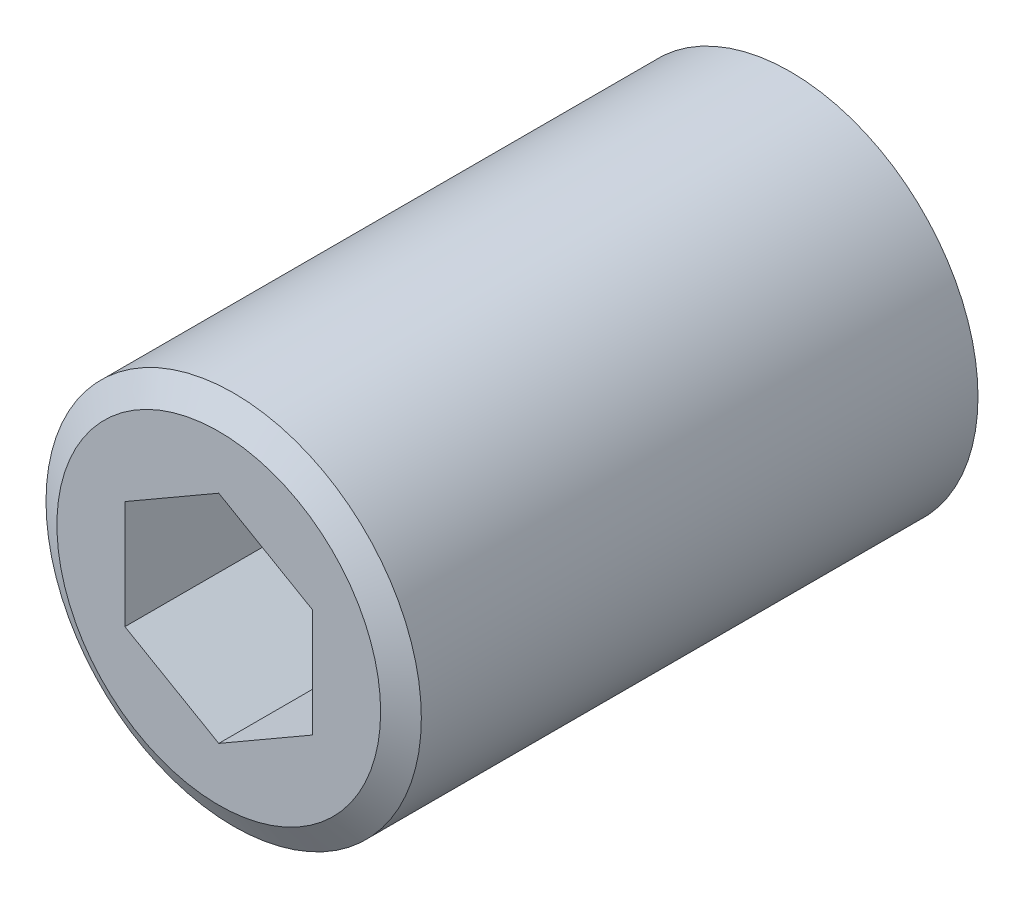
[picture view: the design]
ISO-10303-21;
HEADER;
FILE_DESCRIPTION(('STEP AP214'),'2;1');
FILE_NAME('part.step','',(''),(''),'','','');
FILE_SCHEMA(('AUTOMOTIVE_DESIGN { 1 0 10303 214 1 1 1 1 }'));
ENDSEC;
DATA;
#1=APPLICATION_CONTEXT('core data for automotive mechanical design processes');
#2=APPLICATION_PROTOCOL_DEFINITION('international standard','automotive_design',2000,#1);
#3=PRODUCT_CONTEXT('',#1,'mechanical');
#4=PRODUCT('Part','Part','',(#3));
#5=PRODUCT_RELATED_PRODUCT_CATEGORY('part','',(#4));
#6=PRODUCT_DEFINITION_FORMATION('','',#4);
#7=PRODUCT_DEFINITION_CONTEXT('part definition',#1,'design');
#8=PRODUCT_DEFINITION('design','',#6,#7);
#9=PRODUCT_DEFINITION_SHAPE('','',#8);
#10=(LENGTH_UNIT() NAMED_UNIT(*) SI_UNIT(.MILLI.,.METRE.));
#11=(NAMED_UNIT(*) PLANE_ANGLE_UNIT() SI_UNIT($,.RADIAN.));
#12=(NAMED_UNIT(*) SI_UNIT($,.STERADIAN.) SOLID_ANGLE_UNIT());
#13=UNCERTAINTY_MEASURE_WITH_UNIT(LENGTH_MEASURE(1.E-05),#10,'distance_accuracy_value','');
#14=(GEOMETRIC_REPRESENTATION_CONTEXT(3) GLOBAL_UNCERTAINTY_ASSIGNED_CONTEXT((#13)) GLOBAL_UNIT_ASSIGNED_CONTEXT((#10,
#11,#12)) REPRESENTATION_CONTEXT('',''));
#15=CARTESIAN_POINT('',(0.,0.,0.));
#16=DIRECTION('',(0.,0.,1.));
#17=DIRECTION('',(1.,0.,0.));
#18=AXIS2_PLACEMENT_3D('',#15,#16,#17);
#19=CARTESIAN_POINT('',(1.5,-5.55,0.));
#20=DIRECTION('',(-0.707106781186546,0.,0.707106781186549));
#21=DIRECTION('',(0.707106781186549,0.,0.707106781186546));
#22=AXIS2_PLACEMENT_3D('',#19,#20,#21);
#23=PLANE('',#22);
#24=CARTESIAN_POINT('',(0.,0.,-1.5));
#25=DIRECTION('',(-0.707106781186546,0.,0.707106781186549));
#26=DIRECTION('',(-0.707106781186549,0.,-0.707106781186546));
#27=AXIS2_PLACEMENT_3D('',#24,#25,#26);
#28=ELLIPSE('',#27,7.84888527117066,5.55);
#29=CARTESIAN_POINT('',(3.,4.66931472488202,1.5));
#30=VERTEX_POINT('',#29);
#31=CARTESIAN_POINT('',(2.77,4.80932427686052,1.27));
#32=VERTEX_POINT('',#31);
#33=EDGE_CURVE('E39',#30,#32,#28,.T.);
#34=ORIENTED_EDGE('',*,*,#33,.F.);
#35=DIRECTION('',(0.,1.,0.));
#36=VECTOR('',#35,1.);
#37=CARTESIAN_POINT('',(3.,-5.55,1.5));
#38=LINE('',#37,#36);
#39=CARTESIAN_POINT('',(3.,3.01132144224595,1.5));
#40=VERTEX_POINT('',#39);
#41=EDGE_CURVE('E747',#40,#30,#38,.T.);
#42=ORIENTED_EDGE('',*,*,#41,.F.);
#43=DIRECTION('',(-0.577350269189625,0.577350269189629,-0.577350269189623));
#44=VECTOR('',#43,1.);
#45=CARTESIAN_POINT('',(4.853773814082,1.15754762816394,3.353773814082));
#46=LINE('',#45,#44);
#47=CARTESIAN_POINT('',(1.51132144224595,4.5,0.0113214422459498));
#48=VERTEX_POINT('',#47);
#49=EDGE_CURVE('E390',#40,#48,#46,.T.);
#50=ORIENTED_EDGE('',*,*,#49,.T.);
#51=DIRECTION('',(0.57735026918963,0.57735026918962,0.577350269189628));
#52=VECTOR('',#51,1.);
#53=CARTESIAN_POINT('',(-1.846226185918,1.1424523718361,-3.34622618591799));
#54=LINE('',#53,#52);
#55=CARTESIAN_POINT('',(2.13446219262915,5.12314075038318,0.634462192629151));
#56=VERTEX_POINT('',#55);
#57=EDGE_CURVE('E743',#48,#56,#54,.T.);
#58=ORIENTED_EDGE('',*,*,#57,.T.);
#59=CARTESIAN_POINT('',(0.,0.,-1.5));
#60=DIRECTION('',(-0.707106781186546,0.,0.707106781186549));
#61=DIRECTION('',(0.707106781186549,0.,0.707106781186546));
#62=AXIS2_PLACEMENT_3D('',#59,#60,#61);
#63=ELLIPSE('',#62,7.84888527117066,5.55);
#64=EDGE_CURVE('E800',#32,#56,#63,.T.);
#65=ORIENTED_EDGE('',*,*,#64,.F.);
#66=EDGE_LOOP('',(#34,#42,#50,#58,#65));
#67=FACE_BOUND('',#66,.T.);
#68=ADVANCED_FACE('F15',(#67),#23,.F.);
#69=CARTESIAN_POINT('',(1.5,-5.55,0.));
#70=DIRECTION('',(0.707106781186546,0.,0.707106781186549));
#71=DIRECTION('',(0.707106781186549,0.,-0.707106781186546));
#72=AXIS2_PLACEMENT_3D('',#69,#70,#71);
#73=PLANE('',#72);
#74=CARTESIAN_POINT('',(0.,0.,1.5));
#75=DIRECTION('',(0.707106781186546,0.,0.707106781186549));
#76=DIRECTION('',(0.707106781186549,0.,-0.707106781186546));
#77=AXIS2_PLACEMENT_3D('',#74,#75,#76);
#78=ELLIPSE('',#77,7.84888527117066,5.55);
#79=CARTESIAN_POINT('',(0.22999999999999,5.54523218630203,1.27));
#80=VERTEX_POINT('',#79);
#81=CARTESIAN_POINT('',(0.,5.55,1.5));
#82=VERTEX_POINT('',#81);
#83=EDGE_CURVE('E476',#80,#82,#78,.T.);
#84=ORIENTED_EDGE('',*,*,#83,.F.);
#85=CARTESIAN_POINT('',(0.,0.,1.5));
#86=DIRECTION('',(0.707106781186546,0.,0.707106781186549));
#87=DIRECTION('',(-0.707106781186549,0.,0.707106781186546));
#88=AXIS2_PLACEMENT_3D('',#85,#86,#87);
#89=ELLIPSE('',#88,7.84888527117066,5.55);
#90=CARTESIAN_POINT('',(0.457573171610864,5.53110538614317,1.04242682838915));
#91=VERTEX_POINT('',#90);
#92=EDGE_CURVE('E791',#91,#80,#89,.T.);
#93=ORIENTED_EDGE('',*,*,#92,.F.);
#94=DIRECTION('',(0.57735026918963,-0.57735026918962,-0.577350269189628));
#95=VECTOR('',#94,1.);
#96=CARTESIAN_POINT('',(4.84622618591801,1.1424523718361,-3.34622618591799));
#97=LINE('',#96,#95);
#98=CARTESIAN_POINT('',(1.48867855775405,4.5,0.0113214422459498));
#99=VERTEX_POINT('',#98);
#100=EDGE_CURVE('E735',#91,#99,#97,.T.);
#101=ORIENTED_EDGE('',*,*,#100,.T.);
#102=DIRECTION('',(-0.577350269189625,-0.577350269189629,0.577350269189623));
#103=VECTOR('',#102,1.);
#104=CARTESIAN_POINT('',(-1.853773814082,1.15754762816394,3.353773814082));
#105=LINE('',#104,#103);
#106=CARTESIAN_POINT('',(0.,3.01132144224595,1.5));
#107=VERTEX_POINT('',#106);
#108=EDGE_CURVE('E559',#99,#107,#105,.T.);
#109=ORIENTED_EDGE('',*,*,#108,.T.);
#110=DIRECTION('',(0.,1.,0.));
#111=VECTOR('',#110,1.);
#112=CARTESIAN_POINT('',(0.,-5.55,1.5));
#113=LINE('',#112,#111);
#114=EDGE_CURVE('E753',#107,#82,#113,.T.);
#115=ORIENTED_EDGE('',*,*,#114,.T.);
#116=EDGE_LOOP('',(#84,#93,#101,#109,#115));
#117=FACE_BOUND('',#116,.T.);
#118=ADVANCED_FACE('F968',(#117),#73,.F.);
#119=CARTESIAN_POINT('',(-1.5,-5.55,0.));
#120=DIRECTION('',(-0.707106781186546,0.,0.707106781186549));
#121=DIRECTION('',(0.707106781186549,0.,0.707106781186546));
#122=AXIS2_PLACEMENT_3D('',#119,#120,#121);
#123=PLANE('',#122);
#124=CARTESIAN_POINT('',(0.,0.,1.5));
#125=DIRECTION('',(-0.707106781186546,0.,0.707106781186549));
#126=DIRECTION('',(-0.707106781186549,0.,-0.707106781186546));
#127=AXIS2_PLACEMENT_3D('',#124,#125,#126);
#128=ELLIPSE('',#127,7.84888527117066,5.55);
#129=CARTESIAN_POINT('',(-0.229999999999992,5.54523218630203,1.27));
#130=VERTEX_POINT('',#129);
#131=EDGE_CURVE('E460',#82,#130,#128,.T.);
#132=ORIENTED_EDGE('',*,*,#131,.F.);
#133=ORIENTED_EDGE('',*,*,#114,.F.);
#134=DIRECTION('',(-0.577350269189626,0.577350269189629,-0.577350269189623));
#135=VECTOR('',#134,1.);
#136=CARTESIAN_POINT('',(1.853773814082,1.15754762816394,3.353773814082));
#137=LINE('',#136,#135);
#138=CARTESIAN_POINT('',(-1.48867855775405,4.5,0.0113214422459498));
#139=VERTEX_POINT('',#138);
#140=EDGE_CURVE('E555',#107,#139,#137,.T.);
#141=ORIENTED_EDGE('',*,*,#140,.T.);
#142=DIRECTION('',(0.57735026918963,0.57735026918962,0.577350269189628));
#143=VECTOR('',#142,1.);
#144=CARTESIAN_POINT('',(-4.84622618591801,1.1424523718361,-3.34622618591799));
#145=LINE('',#144,#143);
#146=CARTESIAN_POINT('',(-0.457573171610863,5.53110538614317,1.04242682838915));
#147=VERTEX_POINT('',#146);
#148=EDGE_CURVE('E731',#139,#147,#145,.T.);
#149=ORIENTED_EDGE('',*,*,#148,.T.);
#150=CARTESIAN_POINT('',(0.,0.,1.5));
#151=DIRECTION('',(-0.707106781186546,0.,0.707106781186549));
#152=DIRECTION('',(0.707106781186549,0.,0.707106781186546));
#153=AXIS2_PLACEMENT_3D('',#150,#151,#152);
#154=ELLIPSE('',#153,7.84888527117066,5.55);
#155=EDGE_CURVE('E790',#130,#147,#154,.T.);
#156=ORIENTED_EDGE('',*,*,#155,.F.);
#157=EDGE_LOOP('',(#132,#133,#141,#149,#156));
#158=FACE_BOUND('',#157,.T.);
#159=ADVANCED_FACE('F975',(#158),#123,.F.);
#160=CARTESIAN_POINT('',(-3.,-5.55,1.5));
#161=DIRECTION('',(0.707106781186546,0.,0.707106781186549));
#162=DIRECTION('',(0.707106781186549,0.,-0.707106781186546));
#163=AXIS2_PLACEMENT_3D('',#160,#161,#162);
#164=PLANE('',#163);
#165=CARTESIAN_POINT('',(0.,0.,-1.5));
#166=DIRECTION('',(0.707106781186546,0.,0.707106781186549));
#167=DIRECTION('',(0.707106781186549,0.,-0.707106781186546));
#168=AXIS2_PLACEMENT_3D('',#165,#166,#167);
#169=ELLIPSE('',#168,7.84888527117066,5.55);
#170=CARTESIAN_POINT('',(-2.77,4.80932427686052,1.27));
#171=VERTEX_POINT('',#170);
#172=CARTESIAN_POINT('',(-3.,4.66931472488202,1.5));
#173=VERTEX_POINT('',#172);
#174=EDGE_CURVE('E472',#171,#173,#169,.T.);
#175=ORIENTED_EDGE('',*,*,#174,.F.);
#176=CARTESIAN_POINT('',(0.,0.,-1.5));
#177=DIRECTION('',(0.707106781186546,0.,0.707106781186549));
#178=DIRECTION('',(-0.707106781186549,0.,0.707106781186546));
#179=AXIS2_PLACEMENT_3D('',#176,#177,#178);
#180=ELLIPSE('',#179,7.84888527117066,5.55);
#181=CARTESIAN_POINT('',(-2.13446219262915,5.12314075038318,0.634462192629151));
#182=VERTEX_POINT('',#181);
#183=EDGE_CURVE('E781',#182,#171,#180,.T.);
#184=ORIENTED_EDGE('',*,*,#183,.F.);
#185=DIRECTION('',(0.57735026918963,-0.57735026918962,-0.577350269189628));
#186=VECTOR('',#185,1.);
#187=CARTESIAN_POINT('',(0.846226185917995,2.14245237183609,-2.34622618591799));
#188=LINE('',#187,#186);
#189=CARTESIAN_POINT('',(-1.51132144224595,4.5,0.0113214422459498));
#190=VERTEX_POINT('',#189);
#191=EDGE_CURVE('E897',#182,#190,#188,.T.);
#192=ORIENTED_EDGE('',*,*,#191,.T.);
#193=DIRECTION('',(-0.577350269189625,-0.577350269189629,0.577350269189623));
#194=VECTOR('',#193,1.);
#195=CARTESIAN_POINT('',(-5.853773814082,0.157547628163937,4.353773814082));
#196=LINE('',#195,#194);
#197=CARTESIAN_POINT('',(-3.,3.01132144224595,1.5));
#198=VERTEX_POINT('',#197);
#199=EDGE_CURVE('E547',#190,#198,#196,.T.);
#200=ORIENTED_EDGE('',*,*,#199,.T.);
#201=DIRECTION('',(0.,1.,0.));
#202=VECTOR('',#201,1.);
#203=CARTESIAN_POINT('',(-3.,-5.55,1.5));
#204=LINE('',#203,#202);
#205=EDGE_CURVE('E758',#198,#173,#204,.T.);
#206=ORIENTED_EDGE('',*,*,#205,.T.);
#207=EDGE_LOOP('',(#175,#184,#192,#200,#206));
#208=FACE_BOUND('',#207,.T.);
#209=ADVANCED_FACE('F1110',(#208),#164,.F.);
#210=CARTESIAN_POINT('',(-4.5,-5.55,0.));
#211=DIRECTION('',(-0.707106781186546,0.,0.707106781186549));
#212=DIRECTION('',(0.707106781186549,0.,0.707106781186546));
#213=AXIS2_PLACEMENT_3D('',#210,#211,#212);
#214=PLANE('',#213);
#215=CARTESIAN_POINT('',(0.,0.,4.5));
#216=DIRECTION('',(-0.707106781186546,0.,0.707106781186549));
#217=DIRECTION('',(-0.707106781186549,0.,-0.707106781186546));
#218=AXIS2_PLACEMENT_3D('',#215,#216,#217);
#219=ELLIPSE('',#218,7.84888527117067,5.55);
#220=CARTESIAN_POINT('',(-3.23,4.51326932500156,1.27));
#221=VERTEX_POINT('',#220);
#222=EDGE_CURVE('E31',#173,#221,#219,.T.);
#223=ORIENTED_EDGE('',*,*,#222,.F.);
#224=ORIENTED_EDGE('',*,*,#205,.F.);
#225=DIRECTION('',(-0.577350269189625,0.577350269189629,-0.577350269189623));
#226=VECTOR('',#225,1.);
#227=CARTESIAN_POINT('',(-1.146226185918,1.15754762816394,3.353773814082));
#228=LINE('',#227,#226);
#229=CARTESIAN_POINT('',(-3.91877783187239,3.93009927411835,0.581222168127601));
#230=VERTEX_POINT('',#229);
#231=EDGE_CURVE('E389',#198,#230,#228,.T.);
#232=ORIENTED_EDGE('',*,*,#231,.T.);
#233=CARTESIAN_POINT('',(0.,0.,4.5));
#234=DIRECTION('',(-0.707106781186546,0.,0.707106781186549));
#235=DIRECTION('',(0.707106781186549,0.,0.707106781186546));
#236=AXIS2_PLACEMENT_3D('',#233,#234,#235);
#237=ELLIPSE('',#236,7.84888527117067,5.55);
#238=EDGE_CURVE('E780',#221,#230,#237,.T.);
#239=ORIENTED_EDGE('',*,*,#238,.F.);
#240=EDGE_LOOP('',(#223,#224,#232,#239));
#241=FACE_BOUND('',#240,.T.);
#242=ADVANCED_FACE('F1008',(#241),#214,.F.);
#243=CARTESIAN_POINT('',(3.,-5.55,1.5));
#244=DIRECTION('',(0.707106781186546,0.,0.707106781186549));
#245=DIRECTION('',(0.707106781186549,0.,-0.707106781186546));
#246=AXIS2_PLACEMENT_3D('',#243,#244,#245);
#247=PLANE('',#246);
#248=CARTESIAN_POINT('',(0.,0.,4.5));
#249=DIRECTION('',(0.707106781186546,0.,0.707106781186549));
#250=DIRECTION('',(0.707106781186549,0.,-0.707106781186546));
#251=AXIS2_PLACEMENT_3D('',#248,#249,#250);
#252=ELLIPSE('',#251,7.84888527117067,5.55);
#253=CARTESIAN_POINT('',(3.23,4.51326932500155,1.27));
#254=VERTEX_POINT('',#253);
#255=EDGE_CURVE('E464',#254,#30,#252,.T.);
#256=ORIENTED_EDGE('',*,*,#255,.F.);
#257=CARTESIAN_POINT('',(0.,0.,4.5));
#258=DIRECTION('',(0.707106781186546,0.,0.707106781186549));
#259=DIRECTION('',(-0.707106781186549,0.,0.707106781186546));
#260=AXIS2_PLACEMENT_3D('',#257,#258,#259);
#261=ELLIPSE('',#260,7.84888527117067,5.55);
#262=CARTESIAN_POINT('',(3.91877783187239,3.93009927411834,0.581222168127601));
#263=VERTEX_POINT('',#262);
#264=EDGE_CURVE('E371',#263,#254,#261,.T.);
#265=ORIENTED_EDGE('',*,*,#264,.F.);
#266=DIRECTION('',(-0.577350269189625,-0.577350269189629,0.577350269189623));
#267=VECTOR('',#266,1.);
#268=CARTESIAN_POINT('',(0.146226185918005,0.157547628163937,4.353773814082));
#269=LINE('',#268,#267);
#270=EDGE_CURVE('E387',#263,#40,#269,.T.);
#271=ORIENTED_EDGE('',*,*,#270,.T.);
#272=ORIENTED_EDGE('',*,*,#41,.T.);
#273=EDGE_LOOP('',(#256,#265,#271,#272));
#274=FACE_BOUND('',#273,.T.);
#275=ADVANCED_FACE('F983',(#274),#247,.F.);
#276=CARTESIAN_POINT('',(0.,0.,-1.5));
#277=DIRECTION('',(-0.707106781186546,0.,0.707106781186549));
#278=DIRECTION('',(-0.707106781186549,0.,-0.707106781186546));
#279=AXIS2_PLACEMENT_3D('',#276,#277,#278);
#280=ELLIPSE('',#279,7.84888527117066,5.55);
#281=CARTESIAN_POINT('',(2.77,-4.80932427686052,1.27));
#282=VERTEX_POINT('',#281);
#283=CARTESIAN_POINT('',(3.,-4.66931472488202,1.5));
#284=VERTEX_POINT('',#283);
#285=EDGE_CURVE('E441',#282,#284,#280,.T.);
#286=ORIENTED_EDGE('',*,*,#285,.F.);
#287=CARTESIAN_POINT('',(2.13446219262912,-5.12314075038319,0.634462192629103));
#288=VERTEX_POINT('',#287);
#289=EDGE_CURVE('E796',#288,#282,#63,.T.);
#290=ORIENTED_EDGE('',*,*,#289,.F.);
#291=DIRECTION('',(-0.577350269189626,0.577350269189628,-0.577350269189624));
#292=VECTOR('',#291,1.);
#293=CARTESIAN_POINT('',(1.85377381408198,-4.84245237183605,0.353773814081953));
#294=LINE('',#293,#292);
#295=CARTESIAN_POINT('',(1.51132144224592,-4.5,0.0113214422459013));
#296=VERTEX_POINT('',#295);
#297=EDGE_CURVE('E723',#288,#296,#294,.T.);
#298=ORIENTED_EDGE('',*,*,#297,.T.);
#299=DIRECTION('',(0.577350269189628,0.577350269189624,0.577350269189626));
#300=VECTOR('',#299,1.);
#301=CARTESIAN_POINT('',(1.15377381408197,-4.85754762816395,-0.34622618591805));
#302=LINE('',#301,#300);
#303=CARTESIAN_POINT('',(3.,-3.01132144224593,1.5));
#304=VERTEX_POINT('',#303);
#305=EDGE_CURVE('E513',#296,#304,#302,.T.);
#306=ORIENTED_EDGE('',*,*,#305,.T.);
#307=EDGE_CURVE('E759',#284,#304,#38,.T.);
#308=ORIENTED_EDGE('',*,*,#307,.F.);
#309=EDGE_LOOP('',(#286,#290,#298,#306,#308));
#310=FACE_BOUND('',#309,.T.);
#311=ADVANCED_FACE('F970',(#310),#23,.F.);
#312=CARTESIAN_POINT('',(0.,0.,1.5));
#313=DIRECTION('',(0.707106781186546,0.,0.707106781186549));
#314=DIRECTION('',(0.707106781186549,0.,-0.707106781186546));
#315=AXIS2_PLACEMENT_3D('',#312,#313,#314);
#316=ELLIPSE('',#315,7.84888527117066,5.55);
#317=CARTESIAN_POINT('',(0.,-5.55,1.5));
#318=VERTEX_POINT('',#317);
#319=CARTESIAN_POINT('',(0.22999999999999,-5.54523218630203,1.27));
#320=VERTEX_POINT('',#319);
#321=EDGE_CURVE('E456',#318,#320,#316,.T.);
#322=ORIENTED_EDGE('',*,*,#321,.F.);
#323=CARTESIAN_POINT('',(0.,-3.01132144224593,1.5));
#324=VERTEX_POINT('',#323);
#325=EDGE_CURVE('E748',#318,#324,#113,.T.);
#326=ORIENTED_EDGE('',*,*,#325,.T.);
#327=DIRECTION('',(0.577350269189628,-0.577350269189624,-0.577350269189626));
#328=VECTOR('',#327,1.);
#329=CARTESIAN_POINT('',(1.84622618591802,-4.85754762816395,-0.34622618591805));
#330=LINE('',#329,#328);
#331=CARTESIAN_POINT('',(1.48867855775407,-4.5,0.0113214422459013));
#332=VERTEX_POINT('',#331);
#333=EDGE_CURVE('E537',#324,#332,#330,.T.);
#334=ORIENTED_EDGE('',*,*,#333,.T.);
#335=DIRECTION('',(-0.577350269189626,-0.577350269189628,0.577350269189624));
#336=VECTOR('',#335,1.);
#337=CARTESIAN_POINT('',(1.14622618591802,-4.84245237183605,0.353773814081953));
#338=LINE('',#337,#336);
#339=CARTESIAN_POINT('',(0.457573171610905,-5.53110538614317,1.0424268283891));
#340=VERTEX_POINT('',#339);
#341=EDGE_CURVE('E715',#332,#340,#338,.T.);
#342=ORIENTED_EDGE('',*,*,#341,.T.);
#343=EDGE_CURVE('E795',#320,#340,#89,.T.);
#344=ORIENTED_EDGE('',*,*,#343,.F.);
#345=EDGE_LOOP('',(#322,#326,#334,#342,#344));
#346=FACE_BOUND('',#345,.T.);
#347=ADVANCED_FACE('F978',(#346),#73,.F.);
#348=CARTESIAN_POINT('',(0.,0.,1.5));
#349=DIRECTION('',(-0.707106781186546,0.,0.707106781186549));
#350=DIRECTION('',(-0.707106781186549,0.,-0.707106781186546));
#351=AXIS2_PLACEMENT_3D('',#348,#349,#350);
#352=ELLIPSE('',#351,7.84888527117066,5.55);
#353=CARTESIAN_POINT('',(-0.229999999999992,-5.54523218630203,1.27));
#354=VERTEX_POINT('',#353);
#355=EDGE_CURVE('E452',#354,#318,#352,.T.);
#356=ORIENTED_EDGE('',*,*,#355,.F.);
#357=CARTESIAN_POINT('',(-0.457573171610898,-5.53110538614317,1.0424268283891));
#358=VERTEX_POINT('',#357);
#359=EDGE_CURVE('E786',#358,#354,#154,.T.);
#360=ORIENTED_EDGE('',*,*,#359,.F.);
#361=DIRECTION('',(-0.577350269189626,0.577350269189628,-0.577350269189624));
#362=VECTOR('',#361,1.);
#363=CARTESIAN_POINT('',(-1.14622618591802,-4.84245237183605,0.353773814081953));
#364=LINE('',#363,#362);
#365=CARTESIAN_POINT('',(-1.48867855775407,-4.5,0.0113214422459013));
#366=VERTEX_POINT('',#365);
#367=EDGE_CURVE('E711',#358,#366,#364,.T.);
#368=ORIENTED_EDGE('',*,*,#367,.T.);
#369=DIRECTION('',(0.577350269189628,0.577350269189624,0.577350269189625));
#370=VECTOR('',#369,1.);
#371=CARTESIAN_POINT('',(-1.84622618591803,-4.85754762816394,-0.34622618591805));
#372=LINE('',#371,#370);
#373=EDGE_CURVE('E533',#366,#324,#372,.T.);
#374=ORIENTED_EDGE('',*,*,#373,.T.);
#375=ORIENTED_EDGE('',*,*,#325,.F.);
#376=EDGE_LOOP('',(#356,#360,#368,#374,#375));
#377=FACE_BOUND('',#376,.T.);
#378=ADVANCED_FACE('F1162',(#377),#123,.F.);
#379=CARTESIAN_POINT('',(0.,0.,-1.5));
#380=DIRECTION('',(0.707106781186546,0.,0.707106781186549));
#381=DIRECTION('',(0.707106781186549,0.,-0.707106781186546));
#382=AXIS2_PLACEMENT_3D('',#379,#380,#381);
#383=ELLIPSE('',#382,7.84888527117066,5.55);
#384=CARTESIAN_POINT('',(-3.,-4.66931472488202,1.5));
#385=VERTEX_POINT('',#384);
#386=CARTESIAN_POINT('',(-2.77,-4.80932427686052,1.27));
#387=VERTEX_POINT('',#386);
#388=EDGE_CURVE('E448',#385,#387,#383,.T.);
#389=ORIENTED_EDGE('',*,*,#388,.F.);
#390=CARTESIAN_POINT('',(-3.,-3.01132144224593,1.5));
#391=VERTEX_POINT('',#390);
#392=EDGE_CURVE('E754',#385,#391,#204,.T.);
#393=ORIENTED_EDGE('',*,*,#392,.T.);
#394=DIRECTION('',(0.577350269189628,-0.577350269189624,-0.577350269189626));
#395=VECTOR('',#394,1.);
#396=CARTESIAN_POINT('',(-2.15377381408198,-3.85754762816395,0.653773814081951));
#397=LINE('',#396,#395);
#398=CARTESIAN_POINT('',(-1.51132144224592,-4.5,0.0113214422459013));
#399=VERTEX_POINT('',#398);
#400=EDGE_CURVE('E525',#391,#399,#397,.T.);
#401=ORIENTED_EDGE('',*,*,#400,.T.);
#402=DIRECTION('',(-0.577350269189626,-0.577350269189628,0.577350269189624));
#403=VECTOR('',#402,1.);
#404=CARTESIAN_POINT('',(-2.85377381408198,-5.84245237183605,1.35377381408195));
#405=LINE('',#404,#403);
#406=CARTESIAN_POINT('',(-2.13446219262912,-5.12314075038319,0.634462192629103));
#407=VERTEX_POINT('',#406);
#408=EDGE_CURVE('E893',#399,#407,#405,.T.);
#409=ORIENTED_EDGE('',*,*,#408,.T.);
#410=EDGE_CURVE('E785',#387,#407,#180,.T.);
#411=ORIENTED_EDGE('',*,*,#410,.F.);
#412=EDGE_LOOP('',(#389,#393,#401,#409,#411));
#413=FACE_BOUND('',#412,.T.);
#414=ADVANCED_FACE('F1157',(#413),#164,.F.);
#415=CARTESIAN_POINT('',(0.,0.,4.5));
#416=DIRECTION('',(-0.707106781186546,0.,0.707106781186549));
#417=DIRECTION('',(-0.707106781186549,0.,-0.707106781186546));
#418=AXIS2_PLACEMENT_3D('',#415,#416,#417);
#419=ELLIPSE('',#418,7.84888527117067,5.55);
#420=CARTESIAN_POINT('',(-3.23,-4.51326932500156,1.27));
#421=VERTEX_POINT('',#420);
#422=EDGE_CURVE('E444',#421,#385,#419,.T.);
#423=ORIENTED_EDGE('',*,*,#422,.F.);
#424=CARTESIAN_POINT('',(-3.91877783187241,-3.93009927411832,0.581222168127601));
#425=VERTEX_POINT('',#424);
#426=EDGE_CURVE('E776',#425,#421,#237,.T.);
#427=ORIENTED_EDGE('',*,*,#426,.F.);
#428=DIRECTION('',(0.577350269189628,0.577350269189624,0.577350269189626));
#429=VECTOR('',#428,1.);
#430=CARTESIAN_POINT('',(-4.84622618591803,-4.85754762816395,-0.34622618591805));
#431=LINE('',#430,#429);
#432=EDGE_CURVE('E521',#425,#391,#431,.T.);
#433=ORIENTED_EDGE('',*,*,#432,.T.);
#434=ORIENTED_EDGE('',*,*,#392,.F.);
#435=EDGE_LOOP('',(#423,#427,#433,#434));
#436=FACE_BOUND('',#435,.T.);
#437=ADVANCED_FACE('F1142',(#436),#214,.F.);
#438=CARTESIAN_POINT('',(0.,0.,4.5));
#439=DIRECTION('',(0.707106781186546,0.,0.707106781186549));
#440=DIRECTION('',(0.707106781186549,0.,-0.707106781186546));
#441=AXIS2_PLACEMENT_3D('',#438,#439,#440);
#442=ELLIPSE('',#441,7.84888527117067,5.55);
#443=CARTESIAN_POINT('',(3.23,-4.51326932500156,1.27));
#444=VERTEX_POINT('',#443);
#445=EDGE_CURVE('E438',#284,#444,#442,.T.);
#446=ORIENTED_EDGE('',*,*,#445,.F.);
#447=ORIENTED_EDGE('',*,*,#307,.T.);
#448=DIRECTION('',(0.577350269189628,-0.577350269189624,-0.577350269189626));
#449=VECTOR('',#448,1.);
#450=CARTESIAN_POINT('',(3.84622618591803,-3.85754762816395,0.653773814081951));
#451=LINE('',#450,#449);
#452=CARTESIAN_POINT('',(3.9187778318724,-3.93009927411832,0.581222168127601));
#453=VERTEX_POINT('',#452);
#454=EDGE_CURVE('E871',#304,#453,#451,.T.);
#455=ORIENTED_EDGE('',*,*,#454,.T.);
#456=EDGE_CURVE('E765',#444,#453,#261,.T.);
#457=ORIENTED_EDGE('',*,*,#456,.F.);
#458=EDGE_LOOP('',(#446,#447,#455,#457));
#459=FACE_BOUND('',#458,.T.);
#460=ADVANCED_FACE('F995',(#459),#247,.F.);
#461=CARTESIAN_POINT('',(-5.55,-1.5,0.0113214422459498));
#462=DIRECTION('',(0.,0.707106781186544,0.707106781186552));
#463=DIRECTION('',(0.,0.707106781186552,-0.707106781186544));
#464=AXIS2_PLACEMENT_3D('',#461,#462,#463);
#465=PLANE('',#464);
#466=CARTESIAN_POINT('',(0.,0.,-1.48867855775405));
#467=DIRECTION('',(0.,0.707106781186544,0.707106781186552));
#468=DIRECTION('',(0.,0.707106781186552,-0.707106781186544));
#469=AXIS2_PLACEMENT_3D('',#466,#467,#468);
#470=ELLIPSE('',#469,7.84888527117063,5.55);
#471=CARTESIAN_POINT('',(-4.81582730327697,-2.75867855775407,1.27));
#472=VERTEX_POINT('',#471);
#473=CARTESIAN_POINT('',(-4.66931472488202,-3.,1.5113214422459));
#474=VERTEX_POINT('',#473);
#475=EDGE_CURVE('E420',#472,#474,#470,.T.);
#476=ORIENTED_EDGE('',*,*,#475,.F.);
#477=CARTESIAN_POINT('',(0.,0.,-1.48867855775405));
#478=DIRECTION('',(0.,0.707106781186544,0.707106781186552));
#479=DIRECTION('',(0.,-0.707106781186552,0.707106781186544));
#480=AXIS2_PLACEMENT_3D('',#477,#478,#479);
#481=ELLIPSE('',#480,7.84888527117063,5.55);
#482=CARTESIAN_POINT('',(-5.1297793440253,-2.11845790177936,0.629779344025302));
#483=VERTEX_POINT('',#482);
#484=EDGE_CURVE('E703',#483,#472,#481,.T.);
#485=ORIENTED_EDGE('',*,*,#484,.F.);
#486=DIRECTION('',(-0.577350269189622,-0.577350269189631,0.577350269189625));
#487=VECTOR('',#486,1.);
#488=CARTESIAN_POINT('',(-6.55377381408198,-3.54245237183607,2.053773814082));
#489=LINE('',#488,#487);
#490=CARTESIAN_POINT('',(-4.51132144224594,-1.5,0.0113214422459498));
#491=VERTEX_POINT('',#490);
#492=EDGE_CURVE('E699',#491,#483,#489,.T.);
#493=ORIENTED_EDGE('',*,*,#492,.F.);
#494=DIRECTION('',(1.,0.,0.));
#495=VECTOR('',#494,1.);
#496=CARTESIAN_POINT('',(-5.55,-1.5,0.0113214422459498));
#497=LINE('',#496,#495);
#498=CARTESIAN_POINT('',(-4.48867855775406,-1.5,0.0113214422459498));
#499=VERTEX_POINT('',#498);
#500=EDGE_CURVE('E487',#491,#499,#497,.T.);
#501=ORIENTED_EDGE('',*,*,#500,.T.);
#502=DIRECTION('',(-0.577350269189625,0.57735026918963,-0.577350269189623));
#503=VECTOR('',#502,1.);
#504=CARTESIAN_POINT('',(-3.14622618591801,-2.84245237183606,1.353773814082));
#505=LINE('',#504,#503);
#506=CARTESIAN_POINT('',(-3.,-2.98867855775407,1.5));
#507=VERTEX_POINT('',#506);
#508=EDGE_CURVE('E675',#507,#499,#505,.T.);
#509=ORIENTED_EDGE('',*,*,#508,.F.);
#510=DIRECTION('',(-0.577350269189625,-0.57735026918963,0.577350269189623));
#511=VECTOR('',#510,1.);
#512=CARTESIAN_POINT('',(-3.85377381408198,-3.84245237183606,2.35377381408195));
#513=LINE('',#512,#511);
#514=CARTESIAN_POINT('',(-1.51132144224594,-1.5,0.0113214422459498));
#515=VERTEX_POINT('',#514);
#516=EDGE_CURVE('E679',#515,#507,#513,.T.);
#517=ORIENTED_EDGE('',*,*,#516,.F.);
#518=CARTESIAN_POINT('',(-1.48867855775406,-1.5,0.0113214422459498));
#519=VERTEX_POINT('',#518);
#520=EDGE_CURVE('E1207',#515,#519,#497,.T.);
#521=ORIENTED_EDGE('',*,*,#520,.T.);
#522=DIRECTION('',(-0.577350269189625,0.577350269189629,-0.577350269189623));
#523=VECTOR('',#522,1.);
#524=CARTESIAN_POINT('',(-0.146226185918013,-2.84245237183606,1.353773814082));
#525=LINE('',#524,#523);
#526=CARTESIAN_POINT('',(0.,-2.98867855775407,1.5));
#527=VERTEX_POINT('',#526);
#528=EDGE_CURVE('E683',#527,#519,#525,.T.);
#529=ORIENTED_EDGE('',*,*,#528,.F.);
#530=DIRECTION('',(-0.577350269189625,-0.57735026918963,0.577350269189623));
#531=VECTOR('',#530,1.);
#532=CARTESIAN_POINT('',(0.146226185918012,-2.84245237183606,1.353773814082));
#533=LINE('',#532,#531);
#534=CARTESIAN_POINT('',(1.48867855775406,-1.5,0.0113214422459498));
#535=VERTEX_POINT('',#534);
#536=EDGE_CURVE('E687',#535,#527,#533,.T.);
#537=ORIENTED_EDGE('',*,*,#536,.F.);
#538=CARTESIAN_POINT('',(1.51132144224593,-1.5,0.0113214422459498));
#539=VERTEX_POINT('',#538);
#540=EDGE_CURVE('E485',#535,#539,#497,.T.);
#541=ORIENTED_EDGE('',*,*,#540,.T.);
#542=DIRECTION('',(-0.577350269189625,0.57735026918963,-0.577350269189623));
#543=VECTOR('',#542,1.);
#544=CARTESIAN_POINT('',(2.85377381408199,-2.84245237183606,1.353773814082));
#545=LINE('',#544,#543);
#546=CARTESIAN_POINT('',(3.,-2.98867855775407,1.5));
#547=VERTEX_POINT('',#546);
#548=EDGE_CURVE('E671',#547,#539,#545,.T.);
#549=ORIENTED_EDGE('',*,*,#548,.F.);
#550=DIRECTION('',(-0.577350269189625,-0.57735026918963,0.577350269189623));
#551=VECTOR('',#550,1.);
#552=CARTESIAN_POINT('',(2.14622618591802,-3.84245237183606,2.35377381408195));
#553=LINE('',#552,#551);
#554=CARTESIAN_POINT('',(4.48867855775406,-1.5,0.0113214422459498));
#555=VERTEX_POINT('',#554);
#556=EDGE_CURVE('E889',#555,#547,#553,.T.);
#557=ORIENTED_EDGE('',*,*,#556,.F.);
#558=CARTESIAN_POINT('',(4.51132144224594,-1.5,0.0113214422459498));
#559=VERTEX_POINT('',#558);
#560=EDGE_CURVE('E481',#555,#559,#497,.T.);
#561=ORIENTED_EDGE('',*,*,#560,.T.);
#562=DIRECTION('',(-0.577350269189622,0.577350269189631,-0.577350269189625));
#563=VECTOR('',#562,1.);
#564=CARTESIAN_POINT('',(5.85377381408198,-2.84245237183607,1.353773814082));
#565=LINE('',#564,#563);
#566=CARTESIAN_POINT('',(5.12977934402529,-2.11845790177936,0.629779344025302));
#567=VERTEX_POINT('',#566);
#568=EDGE_CURVE('E691',#567,#559,#565,.T.);
#569=ORIENTED_EDGE('',*,*,#568,.F.);
#570=CARTESIAN_POINT('',(0.,0.,-1.48867855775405));
#571=DIRECTION('',(0.,0.707106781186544,0.707106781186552));
#572=DIRECTION('',(0.,-0.707106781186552,0.707106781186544));
#573=AXIS2_PLACEMENT_3D('',#570,#571,#572);
#574=ELLIPSE('',#573,7.84888527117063,5.55);
#575=CARTESIAN_POINT('',(4.81582730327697,-2.75867855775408,1.27));
#576=VERTEX_POINT('',#575);
#577=EDGE_CURVE('E695',#576,#567,#574,.T.);
#578=ORIENTED_EDGE('',*,*,#577,.F.);
#579=CARTESIAN_POINT('',(4.66931472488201,-3.,1.5113214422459));
#580=VERTEX_POINT('',#579);
#581=EDGE_CURVE('E399',#580,#576,#470,.T.);
#582=ORIENTED_EDGE('',*,*,#581,.F.);
#583=DIRECTION('',(1.,0.,0.));
#584=VECTOR('',#583,1.);
#585=CARTESIAN_POINT('',(-5.55,-3.,1.5113214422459));
#586=LINE('',#585,#584);
#587=EDGE_CURVE('E480',#474,#580,#586,.T.);
#588=ORIENTED_EDGE('',*,*,#587,.F.);
#589=EDGE_LOOP('',(#476,#485,#493,#501,#509,#517,#521,#529,#537,#541,#549,#557,#561,#569,#578,
#582,#588));
#590=FACE_BOUND('',#589,.T.);
#591=ADVANCED_FACE('F1192',(#590),#465,.F.);
#592=CARTESIAN_POINT('',(-5.55,-1.5,0.0113214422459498));
#593=DIRECTION('',(0.,-0.707106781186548,0.707106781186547));
#594=DIRECTION('',(0.,0.707106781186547,0.707106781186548));
#595=AXIS2_PLACEMENT_3D('',#592,#593,#594);
#596=PLANE('',#595);
#597=CARTESIAN_POINT('',(0.,0.,1.51132144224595));
#598=DIRECTION('',(0.,-0.707106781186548,0.707106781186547));
#599=DIRECTION('',(0.,-0.707106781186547,-0.707106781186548));
#600=AXIS2_PLACEMENT_3D('',#597,#598,#599);
#601=ELLIPSE('',#600,7.84888527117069,5.55);
#602=CARTESIAN_POINT('',(5.5447510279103,-0.241321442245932,1.27));
#603=VERTEX_POINT('',#602);
#604=CARTESIAN_POINT('',(5.55,0.,1.51132144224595));
#605=VERTEX_POINT('',#604);
#606=EDGE_CURVE('E432',#603,#605,#601,.T.);
#607=ORIENTED_EDGE('',*,*,#606,.F.);
#608=CARTESIAN_POINT('',(0.,0.,1.51132144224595));
#609=DIRECTION('',(0.,-0.707106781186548,0.707106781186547));
#610=DIRECTION('',(0.,0.707106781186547,0.707106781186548));
#611=AXIS2_PLACEMENT_3D('',#608,#609,#610);
#612=ELLIPSE('',#611,7.84888527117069,5.55);
#613=CARTESIAN_POINT('',(5.52900247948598,-0.482318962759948,1.029002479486));
#614=VERTEX_POINT('',#613);
#615=EDGE_CURVE('E659',#614,#603,#612,.T.);
#616=ORIENTED_EDGE('',*,*,#615,.F.);
#617=DIRECTION('',(0.577350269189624,0.577350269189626,0.577350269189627));
#618=VECTOR('',#617,1.);
#619=CARTESIAN_POINT('',(3.15377381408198,-2.85754762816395,-1.34622618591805));
#620=LINE('',#619,#618);
#621=EDGE_CURVE('E655',#559,#614,#620,.T.);
#622=ORIENTED_EDGE('',*,*,#621,.F.);
#623=ORIENTED_EDGE('',*,*,#560,.F.);
#624=DIRECTION('',(0.577350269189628,-0.577350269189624,-0.577350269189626));
#625=VECTOR('',#624,1.);
#626=CARTESIAN_POINT('',(4.84622618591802,-1.85754762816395,-0.346226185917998));
#627=LINE('',#626,#625);
#628=CARTESIAN_POINT('',(3.,-0.0113214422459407,1.5));
#629=VERTEX_POINT('',#628);
#630=EDGE_CURVE('E885',#629,#555,#627,.T.);
#631=ORIENTED_EDGE('',*,*,#630,.F.);
#632=DIRECTION('',(0.577350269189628,0.577350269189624,0.577350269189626));
#633=VECTOR('',#632,1.);
#634=CARTESIAN_POINT('',(0.153773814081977,-2.85754762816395,-1.34622618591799));
#635=LINE('',#634,#633);
#636=EDGE_CURVE('E635',#539,#629,#635,.T.);
#637=ORIENTED_EDGE('',*,*,#636,.F.);
#638=ORIENTED_EDGE('',*,*,#540,.F.);
#639=DIRECTION('',(0.577350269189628,-0.577350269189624,-0.577350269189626));
#640=VECTOR('',#639,1.);
#641=CARTESIAN_POINT('',(2.84622618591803,-2.85754762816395,-1.34622618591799));
#642=LINE('',#641,#640);
#643=CARTESIAN_POINT('',(0.,-0.0113214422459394,1.5));
#644=VERTEX_POINT('',#643);
#645=EDGE_CURVE('E651',#644,#535,#642,.T.);
#646=ORIENTED_EDGE('',*,*,#645,.F.);
#647=DIRECTION('',(0.577350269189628,0.577350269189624,0.577350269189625));
#648=VECTOR('',#647,1.);
#649=CARTESIAN_POINT('',(-2.84622618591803,-2.85754762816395,-1.34622618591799));
#650=LINE('',#649,#648);
#651=EDGE_CURVE('E647',#519,#644,#650,.T.);
#652=ORIENTED_EDGE('',*,*,#651,.F.);
#653=ORIENTED_EDGE('',*,*,#520,.F.);
#654=DIRECTION('',(0.577350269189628,-0.577350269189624,-0.577350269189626));
#655=VECTOR('',#654,1.);
#656=CARTESIAN_POINT('',(-1.15377381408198,-1.85754762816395,-0.346226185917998));
#657=LINE('',#656,#655);
#658=CARTESIAN_POINT('',(-3.,-0.0113214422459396,1.5));
#659=VERTEX_POINT('',#658);
#660=EDGE_CURVE('E643',#659,#515,#657,.T.);
#661=ORIENTED_EDGE('',*,*,#660,.F.);
#662=DIRECTION('',(0.577350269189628,0.577350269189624,0.577350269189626));
#663=VECTOR('',#662,1.);
#664=CARTESIAN_POINT('',(-5.84622618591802,-2.85754762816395,-1.34622618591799));
#665=LINE('',#664,#663);
#666=EDGE_CURVE('E639',#499,#659,#665,.T.);
#667=ORIENTED_EDGE('',*,*,#666,.F.);
#668=ORIENTED_EDGE('',*,*,#500,.F.);
#669=DIRECTION('',(0.577350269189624,-0.577350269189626,-0.577350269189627));
#670=VECTOR('',#669,1.);
#671=CARTESIAN_POINT('',(-3.85377381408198,-2.15754762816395,-0.646226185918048));
#672=LINE('',#671,#670);
#673=CARTESIAN_POINT('',(-5.52900247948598,-0.482318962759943,1.029002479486));
#674=VERTEX_POINT('',#673);
#675=EDGE_CURVE('E663',#674,#491,#672,.T.);
#676=ORIENTED_EDGE('',*,*,#675,.F.);
#677=CARTESIAN_POINT('',(0.,0.,1.51132144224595));
#678=DIRECTION('',(0.,-0.707106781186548,0.707106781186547));
#679=DIRECTION('',(0.,0.707106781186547,0.707106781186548));
#680=AXIS2_PLACEMENT_3D('',#677,#678,#679);
#681=ELLIPSE('',#680,7.84888527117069,5.55);
#682=CARTESIAN_POINT('',(-5.5447510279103,-0.241321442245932,1.27));
#683=VERTEX_POINT('',#682);
#684=EDGE_CURVE('E667',#683,#674,#681,.T.);
#685=ORIENTED_EDGE('',*,*,#684,.F.);
#686=CARTESIAN_POINT('',(-5.55,0.,1.51132144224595));
#687=VERTEX_POINT('',#686);
#688=EDGE_CURVE('E437',#687,#683,#601,.T.);
#689=ORIENTED_EDGE('',*,*,#688,.F.);
#690=DIRECTION('',(1.,0.,0.));
#691=VECTOR('',#690,1.);
#692=CARTESIAN_POINT('',(-5.55,0.,1.51132144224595));
#693=LINE('',#692,#691);
#694=EDGE_CURVE('E486',#687,#605,#693,.T.);
#695=ORIENTED_EDGE('',*,*,#694,.T.);
#696=EDGE_LOOP('',(#607,#616,#622,#623,#631,#637,#638,#646,#652,#653,#661,#667,#668,#676,#685,
#689,#695));
#697=FACE_BOUND('',#696,.T.);
#698=ADVANCED_FACE('F1201',(#697),#596,.F.);
#699=CARTESIAN_POINT('',(-5.55,1.5,0.0113214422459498));
#700=DIRECTION('',(0.,0.707106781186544,0.707106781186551));
#701=DIRECTION('',(0.,0.707106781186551,-0.707106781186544));
#702=AXIS2_PLACEMENT_3D('',#699,#700,#701);
#703=PLANE('',#702);
#704=CARTESIAN_POINT('',(0.,0.,1.51132144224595));
#705=DIRECTION('',(0.,0.707106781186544,0.707106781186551));
#706=DIRECTION('',(0.,0.707106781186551,-0.707106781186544));
#707=AXIS2_PLACEMENT_3D('',#704,#705,#706);
#708=ELLIPSE('',#707,7.84888527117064,5.55);
#709=CARTESIAN_POINT('',(-5.5447510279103,0.241321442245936,1.27));
#710=VERTEX_POINT('',#709);
#711=EDGE_CURVE('E433',#710,#687,#708,.T.);
#712=ORIENTED_EDGE('',*,*,#711,.F.);
#713=CARTESIAN_POINT('',(0.,0.,1.51132144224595));
#714=DIRECTION('',(0.,0.707106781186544,0.707106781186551));
#715=DIRECTION('',(0.,-0.707106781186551,0.707106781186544));
#716=AXIS2_PLACEMENT_3D('',#713,#714,#715);
#717=ELLIPSE('',#716,7.84888527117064,5.55);
#718=CARTESIAN_POINT('',(-5.52900247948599,0.482318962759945,1.029002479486));
#719=VERTEX_POINT('',#718);
#720=EDGE_CURVE('E631',#719,#710,#717,.T.);
#721=ORIENTED_EDGE('',*,*,#720,.F.);
#722=DIRECTION('',(-0.577350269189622,-0.57735026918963,0.577350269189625));
#723=VECTOR('',#722,1.);
#724=CARTESIAN_POINT('',(-7.55377381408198,-1.54245237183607,3.053773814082));
#725=LINE('',#724,#723);
#726=CARTESIAN_POINT('',(-4.51132144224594,1.5,0.0113214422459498));
#727=VERTEX_POINT('',#726);
#728=EDGE_CURVE('E627',#727,#719,#725,.T.);
#729=ORIENTED_EDGE('',*,*,#728,.F.);
#730=DIRECTION('',(1.,0.,0.));
#731=VECTOR('',#730,1.);
#732=CARTESIAN_POINT('',(-5.55,1.5,0.0113214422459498));
#733=LINE('',#732,#731);
#734=CARTESIAN_POINT('',(-4.48867855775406,1.5,0.0113214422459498));
#735=VERTEX_POINT('',#734);
#736=EDGE_CURVE('E491',#727,#735,#733,.T.);
#737=ORIENTED_EDGE('',*,*,#736,.T.);
#738=DIRECTION('',(-0.577350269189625,0.577350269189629,-0.577350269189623));
#739=VECTOR('',#738,1.);
#740=CARTESIAN_POINT('',(-2.146226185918,-0.842452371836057,2.35377381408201));
#741=LINE('',#740,#739);
#742=CARTESIAN_POINT('',(-3.,0.0113214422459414,1.5));
#743=VERTEX_POINT('',#742);
#744=EDGE_CURVE('E603',#743,#735,#741,.T.);
#745=ORIENTED_EDGE('',*,*,#744,.F.);
#746=DIRECTION('',(-0.577350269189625,-0.577350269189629,0.577350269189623));
#747=VECTOR('',#746,1.);
#748=CARTESIAN_POINT('',(-4.85377381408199,-1.84245237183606,3.35377381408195));
#749=LINE('',#748,#747);
#750=CARTESIAN_POINT('',(-1.51132144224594,1.5,0.0113214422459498));
#751=VERTEX_POINT('',#750);
#752=EDGE_CURVE('E607',#751,#743,#749,.T.);
#753=ORIENTED_EDGE('',*,*,#752,.F.);
#754=CARTESIAN_POINT('',(-1.48867855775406,1.5,0.0113214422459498));
#755=VERTEX_POINT('',#754);
#756=EDGE_CURVE('E1665',#751,#755,#733,.T.);
#757=ORIENTED_EDGE('',*,*,#756,.T.);
#758=DIRECTION('',(-0.577350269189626,0.577350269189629,-0.577350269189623));
#759=VECTOR('',#758,1.);
#760=CARTESIAN_POINT('',(0.853773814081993,-0.842452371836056,2.35377381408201));
#761=LINE('',#760,#759);
#762=CARTESIAN_POINT('',(0.,0.0113214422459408,1.5));
#763=VERTEX_POINT('',#762);
#764=EDGE_CURVE('E611',#763,#755,#761,.T.);
#765=ORIENTED_EDGE('',*,*,#764,.F.);
#766=DIRECTION('',(-0.577350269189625,-0.577350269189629,0.577350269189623));
#767=VECTOR('',#766,1.);
#768=CARTESIAN_POINT('',(-0.853773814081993,-0.842452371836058,2.35377381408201));
#769=LINE('',#768,#767);
#770=CARTESIAN_POINT('',(1.48867855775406,1.5,0.0113214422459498));
#771=VERTEX_POINT('',#770);
#772=EDGE_CURVE('E615',#771,#763,#769,.T.);
#773=ORIENTED_EDGE('',*,*,#772,.F.);
#774=CARTESIAN_POINT('',(1.51132144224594,1.5,0.0113214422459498));
#775=VERTEX_POINT('',#774);
#776=EDGE_CURVE('E496',#771,#775,#733,.T.);
#777=ORIENTED_EDGE('',*,*,#776,.T.);
#778=DIRECTION('',(-0.577350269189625,0.577350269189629,-0.577350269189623));
#779=VECTOR('',#778,1.);
#780=CARTESIAN_POINT('',(3.853773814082,-0.842452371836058,2.35377381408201));
#781=LINE('',#780,#779);
#782=CARTESIAN_POINT('',(3.,0.0113214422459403,1.5));
#783=VERTEX_POINT('',#782);
#784=EDGE_CURVE('E599',#783,#775,#781,.T.);
#785=ORIENTED_EDGE('',*,*,#784,.F.);
#786=DIRECTION('',(-0.577350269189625,-0.577350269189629,0.577350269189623));
#787=VECTOR('',#786,1.);
#788=CARTESIAN_POINT('',(1.14622618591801,-1.84245237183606,3.35377381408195));
#789=LINE('',#788,#787);
#790=CARTESIAN_POINT('',(4.48867855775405,1.5,0.0113214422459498));
#791=VERTEX_POINT('',#790);
#792=EDGE_CURVE('E881',#791,#783,#789,.T.);
#793=ORIENTED_EDGE('',*,*,#792,.F.);
#794=CARTESIAN_POINT('',(4.51132144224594,1.5,0.0113214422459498));
#795=VERTEX_POINT('',#794);
#796=EDGE_CURVE('E492',#791,#795,#733,.T.);
#797=ORIENTED_EDGE('',*,*,#796,.T.);
#798=DIRECTION('',(-0.577350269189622,0.57735026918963,-0.577350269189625));
#799=VECTOR('',#798,1.);
#800=CARTESIAN_POINT('',(6.85377381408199,-0.842452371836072,2.35377381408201));
#801=LINE('',#800,#799);
#802=CARTESIAN_POINT('',(5.52900247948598,0.482318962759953,1.029002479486));
#803=VERTEX_POINT('',#802);
#804=EDGE_CURVE('E619',#803,#795,#801,.T.);
#805=ORIENTED_EDGE('',*,*,#804,.F.);
#806=CARTESIAN_POINT('',(0.,0.,1.51132144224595));
#807=DIRECTION('',(0.,0.707106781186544,0.707106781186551));
#808=DIRECTION('',(0.,-0.707106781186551,0.707106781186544));
#809=AXIS2_PLACEMENT_3D('',#806,#807,#808);
#810=ELLIPSE('',#809,7.84888527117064,5.55);
#811=CARTESIAN_POINT('',(5.5447510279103,0.241321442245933,1.27));
#812=VERTEX_POINT('',#811);
#813=EDGE_CURVE('E623',#812,#803,#810,.T.);
#814=ORIENTED_EDGE('',*,*,#813,.F.);
#815=EDGE_CURVE('E428',#605,#812,#708,.T.);
#816=ORIENTED_EDGE('',*,*,#815,.F.);
#817=ORIENTED_EDGE('',*,*,#694,.F.);
#818=EDGE_LOOP('',(#712,#721,#729,#737,#745,#753,#757,#765,#773,#777,#785,#793,#797,#805,#814,
#816,#817));
#819=FACE_BOUND('',#818,.T.);
#820=ADVANCED_FACE('F1270',(#819),#703,.F.);
#821=CARTESIAN_POINT('',(-5.55,3.,1.51132144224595));
#822=DIRECTION('',(0.,-0.707106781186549,0.707106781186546));
#823=DIRECTION('',(0.,0.707106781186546,0.707106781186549));
#824=AXIS2_PLACEMENT_3D('',#821,#822,#823);
#825=PLANE('',#824);
#826=CARTESIAN_POINT('',(0.,0.,-1.48867855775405));
#827=DIRECTION('',(0.,-0.707106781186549,0.707106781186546));
#828=DIRECTION('',(0.,-0.707106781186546,-0.707106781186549));
#829=AXIS2_PLACEMENT_3D('',#826,#827,#828);
#830=ELLIPSE('',#829,7.8488852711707,5.55);
#831=CARTESIAN_POINT('',(4.81582730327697,2.75867855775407,1.27));
#832=VERTEX_POINT('',#831);
#833=CARTESIAN_POINT('',(4.66931472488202,3.,1.51132144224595));
#834=VERTEX_POINT('',#833);
#835=EDGE_CURVE('E397',#832,#834,#830,.T.);
#836=ORIENTED_EDGE('',*,*,#835,.F.);
#837=CARTESIAN_POINT('',(0.,0.,-1.4886785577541));
#838=DIRECTION('',(0.,-0.707106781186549,0.707106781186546));
#839=DIRECTION('',(0.,0.707106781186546,0.707106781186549));
#840=AXIS2_PLACEMENT_3D('',#837,#838,#839);
#841=ELLIPSE('',#840,7.8488852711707,5.55);
#842=CARTESIAN_POINT('',(5.12977934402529,2.11845790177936,0.629779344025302));
#843=VERTEX_POINT('',#842);
#844=EDGE_CURVE('E587',#843,#832,#841,.T.);
#845=ORIENTED_EDGE('',*,*,#844,.F.);
#846=DIRECTION('',(0.577350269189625,0.577350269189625,0.577350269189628));
#847=VECTOR('',#846,1.);
#848=CARTESIAN_POINT('',(2.15377381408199,-0.857547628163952,-2.34622618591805));
#849=LINE('',#848,#847);
#850=EDGE_CURVE('E583',#795,#843,#849,.T.);
#851=ORIENTED_EDGE('',*,*,#850,.F.);
#852=ORIENTED_EDGE('',*,*,#796,.F.);
#853=DIRECTION('',(0.577350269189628,-0.577350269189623,-0.577350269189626));
#854=VECTOR('',#853,1.);
#855=CARTESIAN_POINT('',(5.84622618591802,0.142452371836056,-1.34622618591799));
#856=LINE('',#855,#854);
#857=CARTESIAN_POINT('',(3.,2.98867855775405,1.5));
#858=VERTEX_POINT('',#857);
#859=EDGE_CURVE('E877',#858,#791,#856,.T.);
#860=ORIENTED_EDGE('',*,*,#859,.F.);
#861=DIRECTION('',(0.577350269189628,0.577350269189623,0.577350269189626));
#862=VECTOR('',#861,1.);
#863=CARTESIAN_POINT('',(-0.84622618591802,-0.857547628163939,-2.34622618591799));
#864=LINE('',#863,#862);
#865=EDGE_CURVE('E563',#775,#858,#864,.T.);
#866=ORIENTED_EDGE('',*,*,#865,.F.);
#867=ORIENTED_EDGE('',*,*,#776,.F.);
#868=DIRECTION('',(0.577350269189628,-0.577350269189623,-0.577350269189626));
#869=VECTOR('',#868,1.);
#870=CARTESIAN_POINT('',(3.84622618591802,-0.857547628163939,-2.34622618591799));
#871=LINE('',#870,#869);
#872=CARTESIAN_POINT('',(0.,2.98867855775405,1.5));
#873=VERTEX_POINT('',#872);
#874=EDGE_CURVE('E579',#873,#771,#871,.T.);
#875=ORIENTED_EDGE('',*,*,#874,.F.);
#876=DIRECTION('',(0.577350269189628,0.577350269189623,0.577350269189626));
#877=VECTOR('',#876,1.);
#878=CARTESIAN_POINT('',(-3.84622618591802,-0.857547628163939,-2.34622618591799));
#879=LINE('',#878,#877);
#880=EDGE_CURVE('E575',#755,#873,#879,.T.);
#881=ORIENTED_EDGE('',*,*,#880,.F.);
#882=ORIENTED_EDGE('',*,*,#756,.F.);
#883=DIRECTION('',(0.577350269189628,-0.577350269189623,-0.577350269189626));
#884=VECTOR('',#883,1.);
#885=CARTESIAN_POINT('',(-0.153773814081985,0.142452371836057,-1.34622618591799));
#886=LINE('',#885,#884);
#887=CARTESIAN_POINT('',(-3.,2.98867855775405,1.5));
#888=VERTEX_POINT('',#887);
#889=EDGE_CURVE('E571',#888,#751,#886,.T.);
#890=ORIENTED_EDGE('',*,*,#889,.F.);
#891=DIRECTION('',(0.577350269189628,0.577350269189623,0.577350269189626));
#892=VECTOR('',#891,1.);
#893=CARTESIAN_POINT('',(-6.84622618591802,-0.857547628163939,-2.34622618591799));
#894=LINE('',#893,#892);
#895=EDGE_CURVE('E567',#735,#888,#894,.T.);
#896=ORIENTED_EDGE('',*,*,#895,.F.);
#897=ORIENTED_EDGE('',*,*,#736,.F.);
#898=DIRECTION('',(0.577350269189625,-0.577350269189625,-0.577350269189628));
#899=VECTOR('',#898,1.);
#900=CARTESIAN_POINT('',(-2.85377381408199,-0.157547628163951,-1.64622618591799));
#901=LINE('',#900,#899);
#902=CARTESIAN_POINT('',(-5.1297793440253,2.11845790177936,0.629779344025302));
#903=VERTEX_POINT('',#902);
#904=EDGE_CURVE('E591',#903,#727,#901,.T.);
#905=ORIENTED_EDGE('',*,*,#904,.F.);
#906=CARTESIAN_POINT('',(0.,0.,-1.4886785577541));
#907=DIRECTION('',(0.,-0.707106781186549,0.707106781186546));
#908=DIRECTION('',(0.,0.707106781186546,0.707106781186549));
#909=AXIS2_PLACEMENT_3D('',#906,#907,#908);
#910=ELLIPSE('',#909,7.8488852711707,5.55);
#911=CARTESIAN_POINT('',(-4.81582730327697,2.75867855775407,1.27));
#912=VERTEX_POINT('',#911);
#913=EDGE_CURVE('E595',#912,#903,#910,.T.);
#914=ORIENTED_EDGE('',*,*,#913,.F.);
#915=CARTESIAN_POINT('',(-4.66931472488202,3.,1.51132144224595));
#916=VERTEX_POINT('',#915);
#917=EDGE_CURVE('E427',#916,#912,#830,.T.);
#918=ORIENTED_EDGE('',*,*,#917,.F.);
#919=DIRECTION('',(1.,0.,0.));
#920=VECTOR('',#919,1.);
#921=CARTESIAN_POINT('',(-5.55,3.,1.51132144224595));
#922=LINE('',#921,#920);
#923=EDGE_CURVE('E497',#916,#834,#922,.T.);
#924=ORIENTED_EDGE('',*,*,#923,.T.);
#925=EDGE_LOOP('',(#836,#845,#851,#852,#860,#866,#867,#875,#881,#882,#890,#896,#897,#905,#914,
#918,#924));
#926=FACE_BOUND('',#925,.T.);
#927=ADVANCED_FACE('F1267',(#926),#825,.F.);
#928=CARTESIAN_POINT('',(-5.55,4.5,0.0113214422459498));
#929=DIRECTION('',(0.,0.707106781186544,0.707106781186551));
#930=DIRECTION('',(0.,0.707106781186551,-0.707106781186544));
#931=AXIS2_PLACEMENT_3D('',#928,#929,#930);
#932=PLANE('',#931);
#933=CARTESIAN_POINT('',(0.,0.,4.5113214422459));
#934=DIRECTION('',(0.,0.707106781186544,0.707106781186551));
#935=DIRECTION('',(0.,0.707106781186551,-0.707106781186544));
#936=AXIS2_PLACEMENT_3D('',#933,#934,#935);
#937=ELLIPSE('',#936,7.84888527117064,5.55);
#938=CARTESIAN_POINT('',(-4.50514542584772,3.24132144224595,1.27));
#939=VERTEX_POINT('',#938);
#940=EDGE_CURVE('E401',#939,#916,#937,.T.);
#941=ORIENTED_EDGE('',*,*,#940,.F.);
#942=CARTESIAN_POINT('',(0.,0.,4.5113214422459));
#943=DIRECTION('',(0.,0.707106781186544,0.707106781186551));
#944=DIRECTION('',(0.,-0.707106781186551,0.707106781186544));
#945=AXIS2_PLACEMENT_3D('',#942,#943,#944);
#946=ELLIPSE('',#945,7.84888527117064,5.55);
#947=EDGE_CURVE('E551',#230,#939,#946,.T.);
#948=ORIENTED_EDGE('',*,*,#947,.F.);
#949=ORIENTED_EDGE('',*,*,#231,.F.);
#950=ORIENTED_EDGE('',*,*,#199,.F.);
#951=DIRECTION('',(1.,0.,0.));
#952=VECTOR('',#951,1.);
#953=CARTESIAN_POINT('',(-5.55,4.5,0.0113214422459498));
#954=LINE('',#953,#952);
#955=EDGE_CURVE('E500',#190,#139,#954,.T.);
#956=ORIENTED_EDGE('',*,*,#955,.T.);
#957=ORIENTED_EDGE('',*,*,#140,.F.);
#958=ORIENTED_EDGE('',*,*,#108,.F.);
#959=EDGE_CURVE('E501',#99,#48,#954,.T.);
#960=ORIENTED_EDGE('',*,*,#959,.T.);
#961=ORIENTED_EDGE('',*,*,#49,.F.);
#962=ORIENTED_EDGE('',*,*,#270,.F.);
#963=CARTESIAN_POINT('',(0.,0.,4.5113214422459));
#964=DIRECTION('',(0.,0.707106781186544,0.707106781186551));
#965=DIRECTION('',(0.,-0.707106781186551,0.707106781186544));
#966=AXIS2_PLACEMENT_3D('',#963,#964,#965);
#967=ELLIPSE('',#966,7.84888527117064,5.55);
#968=CARTESIAN_POINT('',(4.50514542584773,3.24132144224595,1.27));
#969=VERTEX_POINT('',#968);
#970=EDGE_CURVE('E369',#969,#263,#967,.T.);
#971=ORIENTED_EDGE('',*,*,#970,.F.);
#972=EDGE_CURVE('E384',#834,#969,#937,.T.);
#973=ORIENTED_EDGE('',*,*,#972,.F.);
#974=ORIENTED_EDGE('',*,*,#923,.F.);
#975=EDGE_LOOP('',(#941,#948,#949,#950,#956,#957,#958,#960,#961,#962,#971,#973,#974));
#976=FACE_BOUND('',#975,.T.);
#977=ADVANCED_FACE('F383',(#976),#932,.F.);
#978=CARTESIAN_POINT('',(-5.55,-3.,1.5113214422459));
#979=DIRECTION('',(0.,-0.707106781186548,0.707106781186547));
#980=DIRECTION('',(0.,0.707106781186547,0.707106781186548));
#981=AXIS2_PLACEMENT_3D('',#978,#979,#980);
#982=PLANE('',#981);
#983=CARTESIAN_POINT('',(0.,0.,4.51132144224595));
#984=DIRECTION('',(0.,-0.707106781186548,0.707106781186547));
#985=DIRECTION('',(0.,-0.707106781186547,-0.707106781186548));
#986=AXIS2_PLACEMENT_3D('',#983,#984,#985);
#987=ELLIPSE('',#986,7.84888527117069,5.55);
#988=CARTESIAN_POINT('',(4.50514542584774,-3.24132144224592,1.27));
#989=VERTEX_POINT('',#988);
#990=EDGE_CURVE('E904',#989,#580,#987,.T.);
#991=ORIENTED_EDGE('',*,*,#990,.F.);
#992=CARTESIAN_POINT('',(0.,0.,4.51132144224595));
#993=DIRECTION('',(0.,-0.707106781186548,0.707106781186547));
#994=DIRECTION('',(0.,0.707106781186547,0.707106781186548));
#995=AXIS2_PLACEMENT_3D('',#992,#993,#994);
#996=ELLIPSE('',#995,7.84888527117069,5.55);
#997=EDGE_CURVE('E517',#453,#989,#996,.T.);
#998=ORIENTED_EDGE('',*,*,#997,.F.);
#999=ORIENTED_EDGE('',*,*,#454,.F.);
#1000=ORIENTED_EDGE('',*,*,#305,.F.);
#1001=DIRECTION('',(1.,0.,0.));
#1002=VECTOR('',#1001,1.);
#1003=CARTESIAN_POINT('',(-5.55,-4.5,0.0113214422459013));
#1004=LINE('',#1003,#1002);
#1005=EDGE_CURVE('E506',#332,#296,#1004,.T.);
#1006=ORIENTED_EDGE('',*,*,#1005,.F.);
#1007=ORIENTED_EDGE('',*,*,#333,.F.);
#1008=ORIENTED_EDGE('',*,*,#373,.F.);
#1009=EDGE_CURVE('E505',#399,#366,#1004,.T.);
#1010=ORIENTED_EDGE('',*,*,#1009,.F.);
#1011=ORIENTED_EDGE('',*,*,#400,.F.);
#1012=ORIENTED_EDGE('',*,*,#432,.F.);
#1013=CARTESIAN_POINT('',(0.,0.,4.51132144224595));
#1014=DIRECTION('',(0.,-0.707106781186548,0.707106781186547));
#1015=DIRECTION('',(0.,0.707106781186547,0.707106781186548));
#1016=AXIS2_PLACEMENT_3D('',#1013,#1014,#1015);
#1017=ELLIPSE('',#1016,7.84888527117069,5.55);
#1018=CARTESIAN_POINT('',(-4.50514542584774,-3.24132144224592,1.27));
#1019=VERTEX_POINT('',#1018);
#1020=EDGE_CURVE('E529',#1019,#425,#1017,.T.);
#1021=ORIENTED_EDGE('',*,*,#1020,.F.);
#1022=EDGE_CURVE('E901',#474,#1019,#987,.T.);
#1023=ORIENTED_EDGE('',*,*,#1022,.F.);
#1024=ORIENTED_EDGE('',*,*,#587,.T.);
#1025=EDGE_LOOP('',(#991,#998,#999,#1000,#1006,#1007,#1008,#1010,#1011,#1012,#1021,#1023,#1024));
#1026=FACE_BOUND('',#1025,.T.);
#1027=ADVANCED_FACE('F1151',(#1026),#982,.F.);
#1028=CARTESIAN_POINT('',(0.,0.,46.27));
#1029=DIRECTION('',(0.,0.,1.));
#1030=DIRECTION('',(1.,0.,0.));
#1031=AXIS2_PLACEMENT_3D('',#1028,#1029,#1030);
#1032=CYLINDRICAL_SURFACE('',#1031,5.55);
#1033=CARTESIAN_POINT('',(0.,0.,1.27));
#1034=DIRECTION('',(0.,0.,1.));
#1035=DIRECTION('',(1.,0.,0.));
#1036=AXIS2_PLACEMENT_3D('',#1033,#1034,#1035);
#1037=CIRCLE('',#1036,5.55);
#1038=EDGE_CURVE('E377',#812,#832,#1037,.T.);
#1039=ORIENTED_EDGE('',*,*,#1038,.F.);
#1040=ORIENTED_EDGE('',*,*,#813,.T.);
#1041=CARTESIAN_POINT('',(0.,0.,-4.5));
#1042=DIRECTION('',(-0.707106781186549,0.,0.707106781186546));
#1043=DIRECTION('',(0.707106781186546,0.,0.707106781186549));
#1044=AXIS2_PLACEMENT_3D('',#1041,#1042,#1043);
#1045=ELLIPSE('',#1044,7.8488852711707,5.55);
#1046=EDGE_CURVE('E766',#803,#843,#1045,.T.);
#1047=ORIENTED_EDGE('',*,*,#1046,.T.);
#1048=ORIENTED_EDGE('',*,*,#844,.T.);
#1049=EDGE_LOOP('',(#1039,#1040,#1047,#1048));
#1050=FACE_BOUND('',#1049,.T.);
#1051=ADVANCED_FACE('F1254',(#1050),#1032,.T.);
#1052=EDGE_CURVE('E869',#576,#603,#1037,.T.);
#1053=ORIENTED_EDGE('',*,*,#1052,.F.);
#1054=ORIENTED_EDGE('',*,*,#577,.T.);
#1055=EDGE_CURVE('E770',#567,#614,#1045,.T.);
#1056=ORIENTED_EDGE('',*,*,#1055,.T.);
#1057=ORIENTED_EDGE('',*,*,#615,.T.);
#1058=EDGE_LOOP('',(#1053,#1054,#1056,#1057));
#1059=FACE_BOUND('',#1058,.T.);
#1060=ADVANCED_FACE('F1303',(#1059),#1032,.T.);
#1061=EDGE_CURVE('E366',#969,#254,#1037,.T.);
#1062=ORIENTED_EDGE('',*,*,#1061,.F.);
#1063=ORIENTED_EDGE('',*,*,#970,.T.);
#1064=ORIENTED_EDGE('',*,*,#264,.T.);
#1065=EDGE_LOOP('',(#1062,#1063,#1064));
#1066=FACE_BOUND('',#1065,.T.);
#1067=ADVANCED_FACE('F368',(#1066),#1032,.T.);
#1068=CARTESIAN_POINT('',(0.,0.,-4.5));
#1069=DIRECTION('',(0.707106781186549,0.,0.707106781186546));
#1070=DIRECTION('',(-0.707106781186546,0.,0.707106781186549));
#1071=AXIS2_PLACEMENT_3D('',#1068,#1069,#1070);
#1072=ELLIPSE('',#1071,7.8488852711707,5.55);
#1073=EDGE_CURVE('E775',#903,#719,#1072,.T.);
#1074=ORIENTED_EDGE('',*,*,#1073,.T.);
#1075=ORIENTED_EDGE('',*,*,#720,.T.);
#1076=EDGE_CURVE('E1047',#912,#710,#1037,.T.);
#1077=ORIENTED_EDGE('',*,*,#1076,.F.);
#1078=ORIENTED_EDGE('',*,*,#913,.T.);
#1079=EDGE_LOOP('',(#1074,#1075,#1077,#1078));
#1080=FACE_BOUND('',#1079,.T.);
#1081=ADVANCED_FACE('F1316',(#1080),#1032,.T.);
#1082=EDGE_CURVE('E771',#674,#483,#1072,.T.);
#1083=ORIENTED_EDGE('',*,*,#1082,.T.);
#1084=ORIENTED_EDGE('',*,*,#484,.T.);
#1085=EDGE_CURVE('E1056',#683,#472,#1037,.T.);
#1086=ORIENTED_EDGE('',*,*,#1085,.F.);
#1087=ORIENTED_EDGE('',*,*,#684,.T.);
#1088=EDGE_LOOP('',(#1083,#1084,#1086,#1087));
#1089=FACE_BOUND('',#1088,.T.);
#1090=ADVANCED_FACE('F1195',(#1089),#1032,.T.);
#1091=EDGE_CURVE('E1059',#1019,#421,#1037,.T.);
#1092=ORIENTED_EDGE('',*,*,#1091,.F.);
#1093=ORIENTED_EDGE('',*,*,#1020,.T.);
#1094=ORIENTED_EDGE('',*,*,#426,.T.);
#1095=EDGE_LOOP('',(#1092,#1093,#1094));
#1096=FACE_BOUND('',#1095,.T.);
#1097=ADVANCED_FACE('F1148',(#1096),#1032,.T.);
#1098=CARTESIAN_POINT('',(-5.55,-5.55,1.05));
#1099=DIRECTION('',(0.707106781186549,0.,0.707106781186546));
#1100=DIRECTION('',(0.707106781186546,0.,-0.707106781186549));
#1101=AXIS2_PLACEMENT_3D('',#1098,#1099,#1100);
#1102=PLANE('',#1101);
#1103=ORIENTED_EDGE('',*,*,#675,.T.);
#1104=ORIENTED_EDGE('',*,*,#492,.T.);
#1105=ORIENTED_EDGE('',*,*,#1082,.F.);
#1106=EDGE_LOOP('',(#1103,#1104,#1105));
#1107=FACE_BOUND('',#1106,.T.);
#1108=ADVANCED_FACE('F1204',(#1107),#1102,.F.);
#1109=CARTESIAN_POINT('',(4.5,-5.55,0.));
#1110=DIRECTION('',(-0.707106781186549,0.,0.707106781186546));
#1111=DIRECTION('',(0.707106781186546,0.,0.707106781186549));
#1112=AXIS2_PLACEMENT_3D('',#1109,#1110,#1111);
#1113=PLANE('',#1112);
#1114=ORIENTED_EDGE('',*,*,#1055,.F.);
#1115=ORIENTED_EDGE('',*,*,#568,.T.);
#1116=ORIENTED_EDGE('',*,*,#621,.T.);
#1117=EDGE_LOOP('',(#1114,#1115,#1116));
#1118=FACE_BOUND('',#1117,.T.);
#1119=ADVANCED_FACE('F1339',(#1118),#1113,.F.);
#1120=ORIENTED_EDGE('',*,*,#155,.T.);
#1121=CARTESIAN_POINT('',(0.,0.,-4.4886785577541));
#1122=DIRECTION('',(0.,-0.707106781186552,0.707106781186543));
#1123=DIRECTION('',(0.,0.707106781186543,0.707106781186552));
#1124=AXIS2_PLACEMENT_3D('',#1121,#1122,#1123);
#1125=ELLIPSE('',#1124,7.84888527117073,5.55);
#1126=EDGE_CURVE('E727',#147,#182,#1125,.T.);
#1127=ORIENTED_EDGE('',*,*,#1126,.T.);
#1128=ORIENTED_EDGE('',*,*,#183,.T.);
#1129=EDGE_CURVE('E1027',#130,#171,#1037,.T.);
#1130=ORIENTED_EDGE('',*,*,#1129,.F.);
#1131=EDGE_LOOP('',(#1120,#1127,#1128,#1130));
#1132=FACE_BOUND('',#1131,.T.);
#1133=ADVANCED_FACE('F1333',(#1132),#1032,.T.);
#1134=ORIENTED_EDGE('',*,*,#410,.T.);
#1135=CARTESIAN_POINT('',(0.,0.,-4.48867855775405));
#1136=DIRECTION('',(0.,0.707106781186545,0.70710678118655));
#1137=DIRECTION('',(0.,-0.70710678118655,0.707106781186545));
#1138=AXIS2_PLACEMENT_3D('',#1135,#1136,#1137);
#1139=ELLIPSE('',#1138,7.84888527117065,5.55);
#1140=EDGE_CURVE('E707',#407,#358,#1139,.T.);
#1141=ORIENTED_EDGE('',*,*,#1140,.T.);
#1142=ORIENTED_EDGE('',*,*,#359,.T.);
#1143=EDGE_CURVE('E1053',#387,#354,#1037,.T.);
#1144=ORIENTED_EDGE('',*,*,#1143,.F.);
#1145=EDGE_LOOP('',(#1134,#1141,#1142,#1144));
#1146=FACE_BOUND('',#1145,.T.);
#1147=ADVANCED_FACE('F1159',(#1146),#1032,.T.);
#1148=ORIENTED_EDGE('',*,*,#343,.T.);
#1149=CARTESIAN_POINT('',(0.,0.,-4.48867855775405));
#1150=DIRECTION('',(0.,0.707106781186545,0.70710678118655));
#1151=DIRECTION('',(0.,-0.70710678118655,0.707106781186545));
#1152=AXIS2_PLACEMENT_3D('',#1149,#1150,#1151);
#1153=ELLIPSE('',#1152,7.84888527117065,5.55);
#1154=EDGE_CURVE('E719',#340,#288,#1153,.T.);
#1155=ORIENTED_EDGE('',*,*,#1154,.T.);
#1156=ORIENTED_EDGE('',*,*,#289,.T.);
#1157=EDGE_CURVE('E868',#320,#282,#1037,.T.);
#1158=ORIENTED_EDGE('',*,*,#1157,.F.);
#1159=EDGE_LOOP('',(#1148,#1155,#1156,#1158));
#1160=FACE_BOUND('',#1159,.T.);
#1161=ADVANCED_FACE('F1075',(#1160),#1032,.T.);
#1162=ORIENTED_EDGE('',*,*,#64,.T.);
#1163=CARTESIAN_POINT('',(0.,0.,-4.4886785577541));
#1164=DIRECTION('',(0.,-0.707106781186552,0.707106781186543));
#1165=DIRECTION('',(0.,0.707106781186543,0.707106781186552));
#1166=AXIS2_PLACEMENT_3D('',#1163,#1164,#1165);
#1167=ELLIPSE('',#1166,7.84888527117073,5.55);
#1168=EDGE_CURVE('E739',#56,#91,#1167,.T.);
#1169=ORIENTED_EDGE('',*,*,#1168,.T.);
#1170=ORIENTED_EDGE('',*,*,#92,.T.);
#1171=EDGE_CURVE('E870',#32,#80,#1037,.T.);
#1172=ORIENTED_EDGE('',*,*,#1171,.F.);
#1173=EDGE_LOOP('',(#1162,#1169,#1170,#1172));
#1174=FACE_BOUND('',#1173,.T.);
#1175=ADVANCED_FACE('F1364',(#1174),#1032,.T.);
#1176=ORIENTED_EDGE('',*,*,#456,.T.);
#1177=ORIENTED_EDGE('',*,*,#997,.T.);
#1178=EDGE_CURVE('E380',#444,#989,#1037,.T.);
#1179=ORIENTED_EDGE('',*,*,#1178,.F.);
#1180=EDGE_LOOP('',(#1176,#1177,#1179));
#1181=FACE_BOUND('',#1180,.T.);
#1182=ADVANCED_FACE('F928',(#1181),#1032,.T.);
#1183=CARTESIAN_POINT('',(0.,0.,26.27));
#1184=DIRECTION('',(0.,0.,1.));
#1185=DIRECTION('',(1.,0.,0.));
#1186=AXIS2_PLACEMENT_3D('',#1183,#1184,#1185);
#1187=PLANE('',#1186);
#1188=CARTESIAN_POINT('',(0.,0.,26.27));
#1189=DIRECTION('',(0.,0.,1.));
#1190=DIRECTION('',(1.,0.,0.));
#1191=AXIS2_PLACEMENT_3D('',#1188,#1189,#1190);
#1192=CIRCLE('',#1191,6.9);
#1193=CARTESIAN_POINT('',(6.9,0.,26.27));
#1194=VERTEX_POINT('',#1193);
#1195=EDGE_CURVE('E905',#1194,#1194,#1192,.T.);
#1196=ORIENTED_EDGE('',*,*,#1195,.T.);
#1197=EDGE_LOOP('',(#1196));
#1198=FACE_BOUND('',#1197,.T.);
#1199=DIRECTION('',(0.86602540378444,-0.5,0.));
#1200=VECTOR('',#1199,1.);
#1201=CARTESIAN_POINT('',(-4.,-2.30940107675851,26.27));
#1202=LINE('',#1201,#1200);
#1203=CARTESIAN_POINT('',(-4.,-2.30940107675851,26.27));
#1204=VERTEX_POINT('',#1203);
#1205=CARTESIAN_POINT('',(0.,-4.618802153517,26.27));
#1206=VERTEX_POINT('',#1205);
#1207=EDGE_CURVE('E801',#1204,#1206,#1202,.T.);
#1208=ORIENTED_EDGE('',*,*,#1207,.F.);
#1209=DIRECTION('',(0.,-1.,0.));
#1210=VECTOR('',#1209,1.);
#1211=CARTESIAN_POINT('',(-4.,2.30940107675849,26.27));
#1212=LINE('',#1211,#1210);
#1213=CARTESIAN_POINT('',(-4.,2.30940107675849,26.27));
#1214=VERTEX_POINT('',#1213);
#1215=EDGE_CURVE('E820',#1214,#1204,#1212,.T.);
#1216=ORIENTED_EDGE('',*,*,#1215,.F.);
#1217=DIRECTION('',(0.866025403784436,0.5,0.));
#1218=VECTOR('',#1217,1.);
#1219=CARTESIAN_POINT('',(-4.,2.30940107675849,26.27));
#1220=LINE('',#1219,#1218);
#1221=CARTESIAN_POINT('',(0.,4.61880215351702,26.27));
#1222=VERTEX_POINT('',#1221);
#1223=EDGE_CURVE('E816',#1214,#1222,#1220,.T.);
#1224=ORIENTED_EDGE('',*,*,#1223,.T.);
#1225=DIRECTION('',(-0.866025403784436,0.5,0.));
#1226=VECTOR('',#1225,1.);
#1227=CARTESIAN_POINT('',(4.,2.30940107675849,26.27));
#1228=LINE('',#1227,#1226);
#1229=CARTESIAN_POINT('',(4.,2.30940107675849,26.27));
#1230=VERTEX_POINT('',#1229);
#1231=EDGE_CURVE('E812',#1230,#1222,#1228,.T.);
#1232=ORIENTED_EDGE('',*,*,#1231,.F.);
#1233=DIRECTION('',(0.,-1.,0.));
#1234=VECTOR('',#1233,1.);
#1235=CARTESIAN_POINT('',(4.,2.30940107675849,26.27));
#1236=LINE('',#1235,#1234);
#1237=CARTESIAN_POINT('',(4.,-2.30940107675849,26.27));
#1238=VERTEX_POINT('',#1237);
#1239=EDGE_CURVE('E808',#1230,#1238,#1236,.T.);
#1240=ORIENTED_EDGE('',*,*,#1239,.T.);
#1241=DIRECTION('',(-0.866025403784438,-0.5,0.));
#1242=VECTOR('',#1241,1.);
#1243=CARTESIAN_POINT('',(4.,-2.30940107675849,26.27));
#1244=LINE('',#1243,#1242);
#1245=EDGE_CURVE('E804',#1238,#1206,#1244,.T.);
#1246=ORIENTED_EDGE('',*,*,#1245,.T.);
#1247=EDGE_LOOP('',(#1208,#1216,#1224,#1232,#1240,#1246));
#1248=FACE_BOUND('',#1247,.T.);
#1249=ADVANCED_FACE('F925',(#1198,#1248),#1187,.T.);
#1250=CARTESIAN_POINT('',(0.,0.,46.27));
#1251=DIRECTION('',(0.,0.,1.));
#1252=DIRECTION('',(1.,0.,0.));
#1253=AXIS2_PLACEMENT_3D('',#1250,#1251,#1252);
#1254=CYLINDRICAL_SURFACE('',#1253,8.);
#1255=CARTESIAN_POINT('',(0.,0.,25.6349147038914));
#1256=DIRECTION('',(0.,0.,1.));
#1257=DIRECTION('',(1.,0.,0.));
#1258=AXIS2_PLACEMENT_3D('',#1255,#1256,#1257);
#1259=CIRCLE('',#1258,8.);
#1260=CARTESIAN_POINT('',(8.,0.,25.6349147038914));
#1261=VERTEX_POINT('',#1260);
#1262=EDGE_CURVE('E24',#1261,#1261,#1259,.F.);
#1263=ORIENTED_EDGE('',*,*,#1262,.T.);
#1264=EDGE_LOOP('',(#1263));
#1265=FACE_BOUND('',#1264,.T.);
#1266=CARTESIAN_POINT('',(0.,0.,1.9050852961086));
#1267=DIRECTION('',(0.,0.,-1.));
#1268=DIRECTION('',(-1.,0.,0.));
#1269=AXIS2_PLACEMENT_3D('',#1266,#1267,#1268);
#1270=CIRCLE('',#1269,8.);
#1271=CARTESIAN_POINT('',(-8.,0.,1.9050852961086));
#1272=VERTEX_POINT('',#1271);
#1273=EDGE_CURVE('E909',#1272,#1272,#1270,.F.);
#1274=ORIENTED_EDGE('',*,*,#1273,.T.);
#1275=EDGE_LOOP('',(#1274));
#1276=FACE_BOUND('',#1275,.T.);
#1277=ADVANCED_FACE('F916',(#1265,#1276),#1254,.T.);
#1278=CARTESIAN_POINT('',(8.,0.,1.27));
#1279=DIRECTION('',(0.,0.,-1.));
#1280=DIRECTION('',(-1.,0.,0.));
#1281=AXIS2_PLACEMENT_3D('',#1278,#1279,#1280);
#1282=PLANE('',#1281);
#1283=CARTESIAN_POINT('',(0.,0.,1.27));
#1284=DIRECTION('',(0.,0.,-1.));
#1285=DIRECTION('',(-1.,0.,0.));
#1286=AXIS2_PLACEMENT_3D('',#1283,#1284,#1285);
#1287=CIRCLE('',#1286,6.9);
#1288=CARTESIAN_POINT('',(-6.9,0.,1.27));
#1289=VERTEX_POINT('',#1288);
#1290=EDGE_CURVE('E9',#1289,#1289,#1287,.T.);
#1291=ORIENTED_EDGE('',*,*,#1290,.T.);
#1292=EDGE_LOOP('',(#1291));
#1293=FACE_BOUND('',#1292,.T.);
#1294=ORIENTED_EDGE('',*,*,#1171,.T.);
#1295=CARTESIAN_POINT('',(0.,0.,1.27));
#1296=DIRECTION('',(0.,0.,-1.));
#1297=DIRECTION('',(-1.,0.,0.));
#1298=AXIS2_PLACEMENT_3D('',#1295,#1296,#1297);
#1299=CIRCLE('',#1298,5.55);
#1300=EDGE_CURVE('E413',#130,#80,#1299,.T.);
#1301=ORIENTED_EDGE('',*,*,#1300,.F.);
#1302=ORIENTED_EDGE('',*,*,#1129,.T.);
#1303=EDGE_CURVE('E1031',#221,#171,#1299,.T.);
#1304=ORIENTED_EDGE('',*,*,#1303,.F.);
#1305=EDGE_CURVE('E1049',#221,#939,#1037,.T.);
#1306=ORIENTED_EDGE('',*,*,#1305,.T.);
#1307=EDGE_CURVE('E421',#912,#939,#1299,.T.);
#1308=ORIENTED_EDGE('',*,*,#1307,.F.);
#1309=ORIENTED_EDGE('',*,*,#1076,.T.);
#1310=EDGE_CURVE('E416',#683,#710,#1299,.T.);
#1311=ORIENTED_EDGE('',*,*,#1310,.F.);
#1312=ORIENTED_EDGE('',*,*,#1085,.T.);
#1313=EDGE_CURVE('E422',#1019,#472,#1299,.T.);
#1314=ORIENTED_EDGE('',*,*,#1313,.F.);
#1315=ORIENTED_EDGE('',*,*,#1091,.T.);
#1316=EDGE_CURVE('E1139',#387,#421,#1299,.T.);
#1317=ORIENTED_EDGE('',*,*,#1316,.F.);
#1318=ORIENTED_EDGE('',*,*,#1143,.T.);
#1319=EDGE_CURVE('E1071',#320,#354,#1299,.T.);
#1320=ORIENTED_EDGE('',*,*,#1319,.F.);
#1321=ORIENTED_EDGE('',*,*,#1157,.T.);
#1322=EDGE_CURVE('E1069',#444,#282,#1299,.T.);
#1323=ORIENTED_EDGE('',*,*,#1322,.F.);
#1324=ORIENTED_EDGE('',*,*,#1178,.T.);
#1325=EDGE_CURVE('E415',#576,#989,#1299,.T.);
#1326=ORIENTED_EDGE('',*,*,#1325,.F.);
#1327=ORIENTED_EDGE('',*,*,#1052,.T.);
#1328=EDGE_CURVE('E408',#812,#603,#1299,.T.);
#1329=ORIENTED_EDGE('',*,*,#1328,.F.);
#1330=ORIENTED_EDGE('',*,*,#1038,.T.);
#1331=EDGE_CURVE('E396',#969,#832,#1299,.T.);
#1332=ORIENTED_EDGE('',*,*,#1331,.F.);
#1333=ORIENTED_EDGE('',*,*,#1061,.T.);
#1334=EDGE_CURVE('E407',#32,#254,#1299,.T.);
#1335=ORIENTED_EDGE('',*,*,#1334,.F.);
#1336=EDGE_LOOP('',(#1294,#1301,#1302,#1304,#1306,#1308,#1309,#1311,#1312,#1314,#1315,#1317,
#1318,#1320,#1321,#1323,#1324,#1326,#1327,#1329,#1330,#1332,#1333,#1335));
#1337=FACE_BOUND('',#1336,.T.);
#1338=ADVANCED_FACE('F404',(#1293,#1337),#1282,.T.);
#1339=ORIENTED_EDGE('',*,*,#238,.T.);
#1340=ORIENTED_EDGE('',*,*,#947,.T.);
#1341=ORIENTED_EDGE('',*,*,#1305,.F.);
#1342=EDGE_LOOP('',(#1339,#1340,#1341));
#1343=FACE_BOUND('',#1342,.T.);
#1344=ADVANCED_FACE('F964',(#1343),#1032,.T.);
#1345=CARTESIAN_POINT('',(-4.,-2.30940107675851,20.27));
#1346=DIRECTION('',(-0.5,-0.86602540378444,0.));
#1347=DIRECTION('',(-0.86602540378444,0.5,0.));
#1348=AXIS2_PLACEMENT_3D('',#1345,#1346,#1347);
#1349=PLANE('',#1348);
#1350=DIRECTION('',(0.,0.,1.));
#1351=VECTOR('',#1350,1.);
#1352=CARTESIAN_POINT('',(-4.,-2.30940107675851,20.27));
#1353=LINE('',#1352,#1351);
#1354=CARTESIAN_POINT('',(-4.,-2.30940107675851,20.27));
#1355=VERTEX_POINT('',#1354);
#1356=EDGE_CURVE('E378',#1355,#1204,#1353,.T.);
#1357=ORIENTED_EDGE('',*,*,#1356,.T.);
#1358=ORIENTED_EDGE('',*,*,#1207,.T.);
#1359=DIRECTION('',(0.,0.,1.));
#1360=VECTOR('',#1359,1.);
#1361=CARTESIAN_POINT('',(0.,-4.618802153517,20.27));
#1362=LINE('',#1361,#1360);
#1363=CARTESIAN_POINT('',(0.,-4.618802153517,20.27));
#1364=VERTEX_POINT('',#1363);
#1365=EDGE_CURVE('E848',#1364,#1206,#1362,.T.);
#1366=ORIENTED_EDGE('',*,*,#1365,.F.);
#1367=DIRECTION('',(0.86602540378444,-0.5,0.));
#1368=VECTOR('',#1367,1.);
#1369=CARTESIAN_POINT('',(-4.,-2.30940107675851,20.27));
#1370=LINE('',#1369,#1368);
#1371=EDGE_CURVE('E824',#1355,#1364,#1370,.T.);
#1372=ORIENTED_EDGE('',*,*,#1371,.F.);
#1373=EDGE_LOOP('',(#1357,#1358,#1366,#1372));
#1374=FACE_BOUND('',#1373,.T.);
#1375=ADVANCED_FACE('F934',(#1374),#1349,.F.);
#1376=CARTESIAN_POINT('',(-4.,2.30940107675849,20.27));
#1377=DIRECTION('',(-1.,0.,0.));
#1378=DIRECTION('',(0.,0.,1.));
#1379=AXIS2_PLACEMENT_3D('',#1376,#1377,#1378);
#1380=PLANE('',#1379);
#1381=DIRECTION('',(0.,0.,1.));
#1382=VECTOR('',#1381,1.);
#1383=CARTESIAN_POINT('',(-4.,2.30940107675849,20.27));
#1384=LINE('',#1383,#1382);
#1385=CARTESIAN_POINT('',(-4.,2.30940107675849,20.27));
#1386=VERTEX_POINT('',#1385);
#1387=EDGE_CURVE('E861',#1386,#1214,#1384,.T.);
#1388=ORIENTED_EDGE('',*,*,#1387,.T.);
#1389=ORIENTED_EDGE('',*,*,#1215,.T.);
#1390=ORIENTED_EDGE('',*,*,#1356,.F.);
#1391=DIRECTION('',(0.,-1.,0.));
#1392=VECTOR('',#1391,1.);
#1393=CARTESIAN_POINT('',(-4.,2.30940107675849,20.27));
#1394=LINE('',#1393,#1392);
#1395=EDGE_CURVE('E844',#1386,#1355,#1394,.T.);
#1396=ORIENTED_EDGE('',*,*,#1395,.F.);
#1397=EDGE_LOOP('',(#1388,#1389,#1390,#1396));
#1398=FACE_BOUND('',#1397,.T.);
#1399=ADVANCED_FACE('F955',(#1398),#1380,.F.);
#1400=CARTESIAN_POINT('',(-4.,2.30940107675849,20.27));
#1401=DIRECTION('',(0.5,-0.866025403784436,0.));
#1402=DIRECTION('',(-0.866025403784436,-0.5,0.));
#1403=AXIS2_PLACEMENT_3D('',#1400,#1401,#1402);
#1404=PLANE('',#1403);
#1405=DIRECTION('',(0.,0.,1.));
#1406=VECTOR('',#1405,1.);
#1407=CARTESIAN_POINT('',(0.,4.61880215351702,20.27));
#1408=LINE('',#1407,#1406);
#1409=CARTESIAN_POINT('',(0.,4.61880215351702,20.27));
#1410=VERTEX_POINT('',#1409);
#1411=EDGE_CURVE('E858',#1410,#1222,#1408,.T.);
#1412=ORIENTED_EDGE('',*,*,#1411,.T.);
#1413=ORIENTED_EDGE('',*,*,#1223,.F.);
#1414=ORIENTED_EDGE('',*,*,#1387,.F.);
#1415=DIRECTION('',(0.866025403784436,0.5,0.));
#1416=VECTOR('',#1415,1.);
#1417=CARTESIAN_POINT('',(-4.,2.30940107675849,20.27));
#1418=LINE('',#1417,#1416);
#1419=EDGE_CURVE('E840',#1386,#1410,#1418,.T.);
#1420=ORIENTED_EDGE('',*,*,#1419,.T.);
#1421=EDGE_LOOP('',(#1412,#1413,#1414,#1420));
#1422=FACE_BOUND('',#1421,.T.);
#1423=ADVANCED_FACE('F952',(#1422),#1404,.T.);
#1424=CARTESIAN_POINT('',(4.,2.30940107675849,20.27));
#1425=DIRECTION('',(0.5,0.866025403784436,0.));
#1426=DIRECTION('',(0.866025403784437,-0.5,0.));
#1427=AXIS2_PLACEMENT_3D('',#1424,#1425,#1426);
#1428=PLANE('',#1427);
#1429=DIRECTION('',(0.,0.,1.));
#1430=VECTOR('',#1429,1.);
#1431=CARTESIAN_POINT('',(4.,2.30940107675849,20.27));
#1432=LINE('',#1431,#1430);
#1433=CARTESIAN_POINT('',(4.,2.30940107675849,20.27));
#1434=VERTEX_POINT('',#1433);
#1435=EDGE_CURVE('E855',#1434,#1230,#1432,.T.);
#1436=ORIENTED_EDGE('',*,*,#1435,.T.);
#1437=ORIENTED_EDGE('',*,*,#1231,.T.);
#1438=ORIENTED_EDGE('',*,*,#1411,.F.);
#1439=DIRECTION('',(-0.866025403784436,0.5,0.));
#1440=VECTOR('',#1439,1.);
#1441=CARTESIAN_POINT('',(4.,2.30940107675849,20.27));
#1442=LINE('',#1441,#1440);
#1443=EDGE_CURVE('E836',#1434,#1410,#1442,.T.);
#1444=ORIENTED_EDGE('',*,*,#1443,.F.);
#1445=EDGE_LOOP('',(#1436,#1437,#1438,#1444));
#1446=FACE_BOUND('',#1445,.T.);
#1447=ADVANCED_FACE('F948',(#1446),#1428,.F.);
#1448=CARTESIAN_POINT('',(4.,2.30940107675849,20.27));
#1449=DIRECTION('',(-1.,0.,0.));
#1450=DIRECTION('',(0.,0.,1.));
#1451=AXIS2_PLACEMENT_3D('',#1448,#1449,#1450);
#1452=PLANE('',#1451);
#1453=DIRECTION('',(0.,0.,1.));
#1454=VECTOR('',#1453,1.);
#1455=CARTESIAN_POINT('',(4.,-2.30940107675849,20.27));
#1456=LINE('',#1455,#1454);
#1457=CARTESIAN_POINT('',(4.,-2.30940107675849,20.27));
#1458=VERTEX_POINT('',#1457);
#1459=EDGE_CURVE('E852',#1458,#1238,#1456,.T.);
#1460=ORIENTED_EDGE('',*,*,#1459,.T.);
#1461=ORIENTED_EDGE('',*,*,#1239,.F.);
#1462=ORIENTED_EDGE('',*,*,#1435,.F.);
#1463=DIRECTION('',(0.,-1.,0.));
#1464=VECTOR('',#1463,1.);
#1465=CARTESIAN_POINT('',(4.,2.30940107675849,20.27));
#1466=LINE('',#1465,#1464);
#1467=EDGE_CURVE('E832',#1434,#1458,#1466,.T.);
#1468=ORIENTED_EDGE('',*,*,#1467,.T.);
#1469=EDGE_LOOP('',(#1460,#1461,#1462,#1468));
#1470=FACE_BOUND('',#1469,.T.);
#1471=ADVANCED_FACE('F944',(#1470),#1452,.T.);
#1472=CARTESIAN_POINT('',(4.,-2.30940107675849,20.27));
#1473=DIRECTION('',(-0.5,0.866025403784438,0.));
#1474=DIRECTION('',(0.866025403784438,0.5,0.));
#1475=AXIS2_PLACEMENT_3D('',#1472,#1473,#1474);
#1476=PLANE('',#1475);
#1477=DIRECTION('',(-0.866025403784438,-0.5,0.));
#1478=VECTOR('',#1477,1.);
#1479=CARTESIAN_POINT('',(4.,-2.30940107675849,20.27));
#1480=LINE('',#1479,#1478);
#1481=EDGE_CURVE('E828',#1458,#1364,#1480,.T.);
#1482=ORIENTED_EDGE('',*,*,#1481,.T.);
#1483=ORIENTED_EDGE('',*,*,#1365,.T.);
#1484=ORIENTED_EDGE('',*,*,#1245,.F.);
#1485=ORIENTED_EDGE('',*,*,#1459,.F.);
#1486=EDGE_LOOP('',(#1482,#1483,#1484,#1485));
#1487=FACE_BOUND('',#1486,.T.);
#1488=ADVANCED_FACE('F937',(#1487),#1476,.T.);
#1489=CARTESIAN_POINT('',(-8.,0.,20.27));
#1490=DIRECTION('',(0.,0.,1.));
#1491=DIRECTION('',(1.,0.,0.));
#1492=AXIS2_PLACEMENT_3D('',#1489,#1490,#1491);
#1493=PLANE('',#1492);
#1494=ORIENTED_EDGE('',*,*,#1371,.T.);
#1495=ORIENTED_EDGE('',*,*,#1481,.F.);
#1496=ORIENTED_EDGE('',*,*,#1467,.F.);
#1497=ORIENTED_EDGE('',*,*,#1443,.T.);
#1498=ORIENTED_EDGE('',*,*,#1419,.F.);
#1499=ORIENTED_EDGE('',*,*,#1395,.T.);
#1500=EDGE_LOOP('',(#1494,#1495,#1496,#1497,#1498,#1499));
#1501=FACE_BOUND('',#1500,.T.);
#1502=ADVANCED_FACE('F941',(#1501),#1493,.T.);
#1503=ORIENTED_EDGE('',*,*,#904,.T.);
#1504=ORIENTED_EDGE('',*,*,#728,.T.);
#1505=ORIENTED_EDGE('',*,*,#1073,.F.);
#1506=EDGE_LOOP('',(#1503,#1504,#1505));
#1507=FACE_BOUND('',#1506,.T.);
#1508=ADVANCED_FACE('F1340',(#1507),#1102,.F.);
#1509=ORIENTED_EDGE('',*,*,#1046,.F.);
#1510=ORIENTED_EDGE('',*,*,#804,.T.);
#1511=ORIENTED_EDGE('',*,*,#850,.T.);
#1512=EDGE_LOOP('',(#1509,#1510,#1511));
#1513=FACE_BOUND('',#1512,.T.);
#1514=ADVANCED_FACE('F1263',(#1513),#1113,.F.);
#1515=CARTESIAN_POINT('',(-5.55,5.55,1.06132144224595));
#1516=DIRECTION('',(0.,-0.707106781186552,0.707106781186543));
#1517=DIRECTION('',(0.,0.707106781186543,0.707106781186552));
#1518=AXIS2_PLACEMENT_3D('',#1515,#1516,#1517);
#1519=PLANE('',#1518);
#1520=ORIENTED_EDGE('',*,*,#959,.F.);
#1521=ORIENTED_EDGE('',*,*,#100,.F.);
#1522=ORIENTED_EDGE('',*,*,#1168,.F.);
#1523=ORIENTED_EDGE('',*,*,#57,.F.);
#1524=EDGE_LOOP('',(#1520,#1521,#1522,#1523));
#1525=FACE_BOUND('',#1524,.T.);
#1526=ADVANCED_FACE('F1260',(#1525),#1519,.F.);
#1527=ORIENTED_EDGE('',*,*,#955,.F.);
#1528=ORIENTED_EDGE('',*,*,#191,.F.);
#1529=ORIENTED_EDGE('',*,*,#1126,.F.);
#1530=ORIENTED_EDGE('',*,*,#148,.F.);
#1531=EDGE_LOOP('',(#1527,#1528,#1529,#1530));
#1532=FACE_BOUND('',#1531,.T.);
#1533=ADVANCED_FACE('F1258',(#1532),#1519,.F.);
#1534=CARTESIAN_POINT('',(-5.55,-4.5,0.0113214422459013));
#1535=DIRECTION('',(0.,0.707106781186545,0.70710678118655));
#1536=DIRECTION('',(0.,0.70710678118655,-0.707106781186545));
#1537=AXIS2_PLACEMENT_3D('',#1534,#1535,#1536);
#1538=PLANE('',#1537);
#1539=ORIENTED_EDGE('',*,*,#1154,.F.);
#1540=ORIENTED_EDGE('',*,*,#341,.F.);
#1541=ORIENTED_EDGE('',*,*,#1005,.T.);
#1542=ORIENTED_EDGE('',*,*,#297,.F.);
#1543=EDGE_LOOP('',(#1539,#1540,#1541,#1542));
#1544=FACE_BOUND('',#1543,.T.);
#1545=ADVANCED_FACE('F1255',(#1544),#1538,.F.);
#1546=ORIENTED_EDGE('',*,*,#1140,.F.);
#1547=ORIENTED_EDGE('',*,*,#408,.F.);
#1548=ORIENTED_EDGE('',*,*,#1009,.T.);
#1549=ORIENTED_EDGE('',*,*,#367,.F.);
#1550=EDGE_LOOP('',(#1546,#1547,#1548,#1549));
#1551=FACE_BOUND('',#1550,.T.);
#1552=ADVANCED_FACE('F996',(#1551),#1538,.F.);
#1553=ORIENTED_EDGE('',*,*,#859,.T.);
#1554=ORIENTED_EDGE('',*,*,#792,.T.);
#1555=EDGE_CURVE('E1013',#783,#858,#38,.T.);
#1556=ORIENTED_EDGE('',*,*,#1555,.T.);
#1557=EDGE_LOOP('',(#1553,#1554,#1556));
#1558=FACE_BOUND('',#1557,.T.);
#1559=ADVANCED_FACE('F988',(#1558),#247,.F.);
#1560=ORIENTED_EDGE('',*,*,#1555,.F.);
#1561=ORIENTED_EDGE('',*,*,#784,.T.);
#1562=ORIENTED_EDGE('',*,*,#865,.T.);
#1563=EDGE_LOOP('',(#1560,#1561,#1562));
#1564=FACE_BOUND('',#1563,.T.);
#1565=ADVANCED_FACE('F971',(#1564),#23,.F.);
#1566=ORIENTED_EDGE('',*,*,#630,.T.);
#1567=ORIENTED_EDGE('',*,*,#556,.T.);
#1568=EDGE_CURVE('E762',#547,#629,#38,.T.);
#1569=ORIENTED_EDGE('',*,*,#1568,.T.);
#1570=EDGE_LOOP('',(#1566,#1567,#1569));
#1571=FACE_BOUND('',#1570,.T.);
#1572=ADVANCED_FACE('F987',(#1571),#247,.F.);
#1573=ORIENTED_EDGE('',*,*,#1568,.F.);
#1574=ORIENTED_EDGE('',*,*,#548,.T.);
#1575=ORIENTED_EDGE('',*,*,#636,.T.);
#1576=EDGE_LOOP('',(#1573,#1574,#1575));
#1577=FACE_BOUND('',#1576,.T.);
#1578=ADVANCED_FACE('F985',(#1577),#23,.F.);
#1579=EDGE_CURVE('E1106',#743,#888,#204,.T.);
#1580=ORIENTED_EDGE('',*,*,#1579,.F.);
#1581=ORIENTED_EDGE('',*,*,#744,.T.);
#1582=ORIENTED_EDGE('',*,*,#895,.T.);
#1583=EDGE_LOOP('',(#1580,#1581,#1582));
#1584=FACE_BOUND('',#1583,.T.);
#1585=ADVANCED_FACE('F1000',(#1584),#214,.F.);
#1586=ORIENTED_EDGE('',*,*,#889,.T.);
#1587=ORIENTED_EDGE('',*,*,#752,.T.);
#1588=ORIENTED_EDGE('',*,*,#1579,.T.);
#1589=EDGE_LOOP('',(#1586,#1587,#1588));
#1590=FACE_BOUND('',#1589,.T.);
#1591=ADVANCED_FACE('F1005',(#1590),#164,.F.);
#1592=EDGE_CURVE('E757',#507,#659,#204,.T.);
#1593=ORIENTED_EDGE('',*,*,#1592,.F.);
#1594=ORIENTED_EDGE('',*,*,#508,.T.);
#1595=ORIENTED_EDGE('',*,*,#666,.T.);
#1596=EDGE_LOOP('',(#1593,#1594,#1595));
#1597=FACE_BOUND('',#1596,.T.);
#1598=ADVANCED_FACE('F1009',(#1597),#214,.F.);
#1599=ORIENTED_EDGE('',*,*,#660,.T.);
#1600=ORIENTED_EDGE('',*,*,#516,.T.);
#1601=ORIENTED_EDGE('',*,*,#1592,.T.);
#1602=EDGE_LOOP('',(#1599,#1600,#1601));
#1603=FACE_BOUND('',#1602,.T.);
#1604=ADVANCED_FACE('F1221',(#1603),#164,.F.);
#1605=EDGE_CURVE('E1099',#763,#873,#113,.T.);
#1606=ORIENTED_EDGE('',*,*,#1605,.F.);
#1607=ORIENTED_EDGE('',*,*,#764,.T.);
#1608=ORIENTED_EDGE('',*,*,#880,.T.);
#1609=EDGE_LOOP('',(#1606,#1607,#1608));
#1610=FACE_BOUND('',#1609,.T.);
#1611=ADVANCED_FACE('F1229',(#1610),#123,.F.);
#1612=ORIENTED_EDGE('',*,*,#874,.T.);
#1613=ORIENTED_EDGE('',*,*,#772,.T.);
#1614=ORIENTED_EDGE('',*,*,#1605,.T.);
#1615=EDGE_LOOP('',(#1612,#1613,#1614));
#1616=FACE_BOUND('',#1615,.T.);
#1617=ADVANCED_FACE('F979',(#1616),#73,.F.);
#1618=EDGE_CURVE('E752',#527,#644,#113,.T.);
#1619=ORIENTED_EDGE('',*,*,#1618,.F.);
#1620=ORIENTED_EDGE('',*,*,#528,.T.);
#1621=ORIENTED_EDGE('',*,*,#651,.T.);
#1622=EDGE_LOOP('',(#1619,#1620,#1621));
#1623=FACE_BOUND('',#1622,.T.);
#1624=ADVANCED_FACE('F1219',(#1623),#123,.F.);
#1625=ORIENTED_EDGE('',*,*,#645,.T.);
#1626=ORIENTED_EDGE('',*,*,#536,.T.);
#1627=ORIENTED_EDGE('',*,*,#1618,.T.);
#1628=EDGE_LOOP('',(#1625,#1626,#1627));
#1629=FACE_BOUND('',#1628,.T.);
#1630=ADVANCED_FACE('F1216',(#1629),#73,.F.);
#1631=CARTESIAN_POINT('',(0.,0.,12.37));
#1632=DIRECTION('',(0.,0.,-1.));
#1633=DIRECTION('',(-1.,0.,0.));
#1634=AXIS2_PLACEMENT_3D('',#1631,#1632,#1633);
#1635=CYLINDRICAL_SURFACE('',#1634,5.55);
#1636=ORIENTED_EDGE('',*,*,#990,.T.);
#1637=ORIENTED_EDGE('',*,*,#581,.T.);
#1638=ORIENTED_EDGE('',*,*,#1325,.T.);
#1639=EDGE_LOOP('',(#1636,#1637,#1638));
#1640=FACE_BOUND('',#1639,.T.);
#1641=ADVANCED_FACE('F1179',(#1640),#1635,.F.);
#1642=ORIENTED_EDGE('',*,*,#1313,.T.);
#1643=ORIENTED_EDGE('',*,*,#475,.T.);
#1644=ORIENTED_EDGE('',*,*,#1022,.T.);
#1645=EDGE_LOOP('',(#1642,#1643,#1644));
#1646=FACE_BOUND('',#1645,.T.);
#1647=ADVANCED_FACE('F1117',(#1646),#1635,.F.);
#1648=ORIENTED_EDGE('',*,*,#1331,.T.);
#1649=ORIENTED_EDGE('',*,*,#835,.T.);
#1650=ORIENTED_EDGE('',*,*,#972,.T.);
#1651=EDGE_LOOP('',(#1648,#1649,#1650));
#1652=FACE_BOUND('',#1651,.T.);
#1653=ADVANCED_FACE('F395',(#1652),#1635,.F.);
#1654=ORIENTED_EDGE('',*,*,#940,.T.);
#1655=ORIENTED_EDGE('',*,*,#917,.T.);
#1656=ORIENTED_EDGE('',*,*,#1307,.T.);
#1657=EDGE_LOOP('',(#1654,#1655,#1656));
#1658=FACE_BOUND('',#1657,.T.);
#1659=ADVANCED_FACE('F1042',(#1658),#1635,.F.);
#1660=ORIENTED_EDGE('',*,*,#606,.T.);
#1661=ORIENTED_EDGE('',*,*,#815,.T.);
#1662=ORIENTED_EDGE('',*,*,#1328,.T.);
#1663=EDGE_LOOP('',(#1660,#1661,#1662));
#1664=FACE_BOUND('',#1663,.T.);
#1665=ADVANCED_FACE('F1128',(#1664),#1635,.F.);
#1666=ORIENTED_EDGE('',*,*,#711,.T.);
#1667=ORIENTED_EDGE('',*,*,#688,.T.);
#1668=ORIENTED_EDGE('',*,*,#1310,.T.);
#1669=EDGE_LOOP('',(#1666,#1667,#1668));
#1670=FACE_BOUND('',#1669,.T.);
#1671=ADVANCED_FACE('F1121',(#1670),#1635,.F.);
#1672=ORIENTED_EDGE('',*,*,#255,.T.);
#1673=ORIENTED_EDGE('',*,*,#33,.T.);
#1674=ORIENTED_EDGE('',*,*,#1334,.T.);
#1675=EDGE_LOOP('',(#1672,#1673,#1674));
#1676=FACE_BOUND('',#1675,.T.);
#1677=ADVANCED_FACE('F1019',(#1676),#1635,.F.);
#1678=ORIENTED_EDGE('',*,*,#1322,.T.);
#1679=ORIENTED_EDGE('',*,*,#285,.T.);
#1680=ORIENTED_EDGE('',*,*,#445,.T.);
#1681=EDGE_LOOP('',(#1678,#1679,#1680));
#1682=FACE_BOUND('',#1681,.T.);
#1683=ADVANCED_FACE('F1120',(#1682),#1635,.F.);
#1684=ORIENTED_EDGE('',*,*,#422,.T.);
#1685=ORIENTED_EDGE('',*,*,#388,.T.);
#1686=ORIENTED_EDGE('',*,*,#1316,.T.);
#1687=EDGE_LOOP('',(#1684,#1685,#1686));
#1688=FACE_BOUND('',#1687,.T.);
#1689=ADVANCED_FACE('F1126',(#1688),#1635,.F.);
#1690=ORIENTED_EDGE('',*,*,#355,.T.);
#1691=ORIENTED_EDGE('',*,*,#321,.T.);
#1692=ORIENTED_EDGE('',*,*,#1319,.T.);
#1693=EDGE_LOOP('',(#1690,#1691,#1692));
#1694=FACE_BOUND('',#1693,.T.);
#1695=ADVANCED_FACE('F1079',(#1694),#1635,.F.);
#1696=ORIENTED_EDGE('',*,*,#1300,.T.);
#1697=ORIENTED_EDGE('',*,*,#83,.T.);
#1698=ORIENTED_EDGE('',*,*,#131,.T.);
#1699=EDGE_LOOP('',(#1696,#1697,#1698));
#1700=FACE_BOUND('',#1699,.T.);
#1701=ADVANCED_FACE('F1029',(#1700),#1635,.F.);
#1702=ORIENTED_EDGE('',*,*,#1303,.T.);
#1703=ORIENTED_EDGE('',*,*,#174,.T.);
#1704=ORIENTED_EDGE('',*,*,#222,.T.);
#1705=EDGE_LOOP('',(#1702,#1703,#1704));
#1706=FACE_BOUND('',#1705,.T.);
#1707=ADVANCED_FACE('F922',(#1706),#1635,.F.);
#1708=CARTESIAN_POINT('',(0.,0.,26.27));
#1709=DIRECTION('',(0.,0.,-1.));
#1710=DIRECTION('',(-1.,0.,0.));
#1711=AXIS2_PLACEMENT_3D('',#1708,#1709,#1710);
#1712=CONICAL_SURFACE('',#1711,6.9,1.0471975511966);
#1713=ORIENTED_EDGE('',*,*,#1262,.F.);
#1714=EDGE_LOOP('',(#1713));
#1715=FACE_BOUND('',#1714,.T.);
#1716=ORIENTED_EDGE('',*,*,#1195,.F.);
#1717=EDGE_LOOP('',(#1716));
#1718=FACE_BOUND('',#1717,.T.);
#1719=ADVANCED_FACE('F919',(#1715,#1718),#1712,.T.);
#1720=CARTESIAN_POINT('',(0.,0.,1.9050852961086));
#1721=DIRECTION('',(0.,0.,1.));
#1722=DIRECTION('',(1.,0.,0.));
#1723=AXIS2_PLACEMENT_3D('',#1720,#1721,#1722);
#1724=CONICAL_SURFACE('',#1723,8.,1.0471975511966);
#1725=ORIENTED_EDGE('',*,*,#1290,.F.);
#1726=EDGE_LOOP('',(#1725));
#1727=FACE_BOUND('',#1726,.T.);
#1728=ORIENTED_EDGE('',*,*,#1273,.F.);
#1729=EDGE_LOOP('',(#1728));
#1730=FACE_BOUND('',#1729,.T.);
#1731=ADVANCED_FACE('F17',(#1727,#1730),#1724,.T.);
#1732=CLOSED_SHELL('',(#68,#118,#159,#209,#242,#275,#311,#347,#378,#414,#437,#460,#591,#698,
#820,#927,#977,#1027,#1051,#1060,#1067,#1081,#1090,#1097,#1108,#1119,#1133,#1147,#1161,#1175,
#1182,#1249,#1277,#1338,#1344,#1375,#1399,#1423,#1447,#1471,#1488,#1502,#1508,#1514,#1526,#1533,
#1545,#1552,#1559,#1565,#1572,#1578,#1585,#1591,#1598,#1604,#1611,#1617,#1624,#1630,#1641,#1647,
#1653,#1659,#1665,#1671,#1677,#1683,#1689,#1695,#1701,#1707,#1719,#1731));
#1733=MANIFOLD_SOLID_BREP('B1',#1732);
#1734=ADVANCED_BREP_SHAPE_REPRESENTATION('',(#18,#1733),#14);
#1735=SHAPE_DEFINITION_REPRESENTATION(#9,#1734);
ENDSEC;
END-ISO-10303-21;
